VERSION 5.4 ;
NAMESCASESENSITIVE ON ;
BUSBITCHARS "[]" ;
DIVIDERCHAR "/" ;
# PATCHED FOR NEBULA: OpenRAM emits 2000 dbu/um, but the sky130hd tech LEF
# declares 1000 and OpenROAD refuses a macro LEF with a finer factor than the
# technology (ODB-0292). Every coordinate in this file has at most three
# decimals, so 1000 dbu/um represents all of them exactly -- nothing is
# snapped or lost. Original kept alongside as <name>.lef.openram_orig.
UNITS
  DATABASE MICRONS 1000 ;
END UNITS
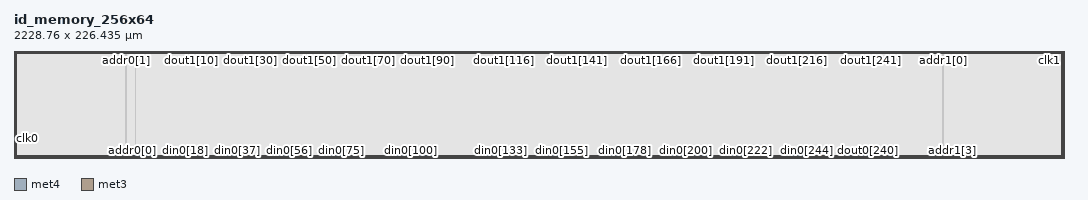
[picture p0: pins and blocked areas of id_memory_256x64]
MACRO id_memory_256x64
   CLASS BLOCK ;
   SIZE 2228.76 BY 226.435 ;
   SYMMETRY X Y R90 ;
   PIN din0[0]
      DIRECTION INPUT ;
      PORT
         LAYER met4 ;
         RECT  257.68 0.0 258.06 0.38 ;
      END
   END din0[0]
   PIN din0[1]
      DIRECTION INPUT ;
      PORT
         LAYER met4 ;
         RECT  263.52 0.0 263.9 0.38 ;
      END
   END din0[1]
   PIN din0[2]
      DIRECTION INPUT ;
      PORT
         LAYER met4 ;
         RECT  269.36 0.0 269.74 0.38 ;
      END
   END din0[2]
   PIN din0[3]
      DIRECTION INPUT ;
      PORT
         LAYER met4 ;
         RECT  275.2 0.0 275.58 0.38 ;
      END
   END din0[3]
   PIN din0[4]
      DIRECTION INPUT ;
      PORT
         LAYER met4 ;
         RECT  281.04 0.0 281.42 0.38 ;
      END
   END din0[4]
   PIN din0[5]
      DIRECTION INPUT ;
      PORT
         LAYER met4 ;
         RECT  286.88 0.0 287.26 0.38 ;
      END
   END din0[5]
   PIN din0[6]
      DIRECTION INPUT ;
      PORT
         LAYER met4 ;
         RECT  292.72 0.0 293.1 0.38 ;
      END
   END din0[6]
   PIN din0[7]
      DIRECTION INPUT ;
      PORT
         LAYER met4 ;
         RECT  298.56 0.0 298.94 0.38 ;
      END
   END din0[7]
   PIN din0[8]
      DIRECTION INPUT ;
      PORT
         LAYER met4 ;
         RECT  304.4 0.0 304.78 0.38 ;
      END
   END din0[8]
   PIN din0[9]
      DIRECTION INPUT ;
      PORT
         LAYER met4 ;
         RECT  310.24 0.0 310.62 0.38 ;
      END
   END din0[9]
   PIN din0[10]
      DIRECTION INPUT ;
      PORT
         LAYER met4 ;
         RECT  316.08 0.0 316.46 0.38 ;
      END
   END din0[10]
   PIN din0[11]
      DIRECTION INPUT ;
      PORT
         LAYER met4 ;
         RECT  321.92 0.0 322.3 0.38 ;
      END
   END din0[11]
   PIN din0[12]
      DIRECTION INPUT ;
      PORT
         LAYER met4 ;
         RECT  327.76 0.0 328.14 0.38 ;
      END
   END din0[12]
   PIN din0[13]
      DIRECTION INPUT ;
      PORT
         LAYER met4 ;
         RECT  333.6 0.0 333.98 0.38 ;
      END
   END din0[13]
   PIN din0[14]
      DIRECTION INPUT ;
      PORT
         LAYER met4 ;
         RECT  339.44 0.0 339.82 0.38 ;
      END
   END din0[14]
   PIN din0[15]
      DIRECTION INPUT ;
      PORT
         LAYER met4 ;
         RECT  345.28 0.0 345.66 0.38 ;
      END
   END din0[15]
   PIN din0[16]
      DIRECTION INPUT ;
      PORT
         LAYER met4 ;
         RECT  351.12 0.0 351.5 0.38 ;
      END
   END din0[16]
   PIN din0[17]
      DIRECTION INPUT ;
      PORT
         LAYER met4 ;
         RECT  356.96 0.0 357.34 0.38 ;
      END
   END din0[17]
   PIN din0[18]
      DIRECTION INPUT ;
      PORT
         LAYER met4 ;
         RECT  362.8 0.0 363.18 0.38 ;
      END
   END din0[18]
   PIN din0[19]
      DIRECTION INPUT ;
      PORT
         LAYER met4 ;
         RECT  368.64 0.0 369.02 0.38 ;
      END
   END din0[19]
   PIN din0[20]
      DIRECTION INPUT ;
      PORT
         LAYER met4 ;
         RECT  374.48 0.0 374.86 0.38 ;
      END
   END din0[20]
   PIN din0[21]
      DIRECTION INPUT ;
      PORT
         LAYER met4 ;
         RECT  380.32 0.0 380.7 0.38 ;
      END
   END din0[21]
   PIN din0[22]
      DIRECTION INPUT ;
      PORT
         LAYER met4 ;
         RECT  386.16 0.0 386.54 0.38 ;
      END
   END din0[22]
   PIN din0[23]
      DIRECTION INPUT ;
      PORT
         LAYER met4 ;
         RECT  392.0 0.0 392.38 0.38 ;
      END
   END din0[23]
   PIN din0[24]
      DIRECTION INPUT ;
      PORT
         LAYER met4 ;
         RECT  397.84 0.0 398.22 0.38 ;
      END
   END din0[24]
   PIN din0[25]
      DIRECTION INPUT ;
      PORT
         LAYER met4 ;
         RECT  403.68 0.0 404.06 0.38 ;
      END
   END din0[25]
   PIN din0[26]
      DIRECTION INPUT ;
      PORT
         LAYER met4 ;
         RECT  409.52 0.0 409.9 0.38 ;
      END
   END din0[26]
   PIN din0[27]
      DIRECTION INPUT ;
      PORT
         LAYER met4 ;
         RECT  415.36 0.0 415.74 0.38 ;
      END
   END din0[27]
   PIN din0[28]
      DIRECTION INPUT ;
      PORT
         LAYER met4 ;
         RECT  421.2 0.0 421.58 0.38 ;
      END
   END din0[28]
   PIN din0[29]
      DIRECTION INPUT ;
      PORT
         LAYER met4 ;
         RECT  427.04 0.0 427.42 0.38 ;
      END
   END din0[29]
   PIN din0[30]
      DIRECTION INPUT ;
      PORT
         LAYER met4 ;
         RECT  432.88 0.0 433.26 0.38 ;
      END
   END din0[30]
   PIN din0[31]
      DIRECTION INPUT ;
      PORT
         LAYER met4 ;
         RECT  438.72 0.0 439.1 0.38 ;
      END
   END din0[31]
   PIN din0[32]
      DIRECTION INPUT ;
      PORT
         LAYER met4 ;
         RECT  444.56 0.0 444.94 0.38 ;
      END
   END din0[32]
   PIN din0[33]
      DIRECTION INPUT ;
      PORT
         LAYER met4 ;
         RECT  450.4 0.0 450.78 0.38 ;
      END
   END din0[33]
   PIN din0[34]
      DIRECTION INPUT ;
      PORT
         LAYER met4 ;
         RECT  456.24 0.0 456.62 0.38 ;
      END
   END din0[34]
   PIN din0[35]
      DIRECTION INPUT ;
      PORT
         LAYER met4 ;
         RECT  462.08 0.0 462.46 0.38 ;
      END
   END din0[35]
   PIN din0[36]
      DIRECTION INPUT ;
      PORT
         LAYER met4 ;
         RECT  467.92 0.0 468.3 0.38 ;
      END
   END din0[36]
   PIN din0[37]
      DIRECTION INPUT ;
      PORT
         LAYER met4 ;
         RECT  473.76 0.0 474.14 0.38 ;
      END
   END din0[37]
   PIN din0[38]
      DIRECTION INPUT ;
      PORT
         LAYER met4 ;
         RECT  479.6 0.0 479.98 0.38 ;
      END
   END din0[38]
   PIN din0[39]
      DIRECTION INPUT ;
      PORT
         LAYER met4 ;
         RECT  485.44 0.0 485.82 0.38 ;
      END
   END din0[39]
   PIN din0[40]
      DIRECTION INPUT ;
      PORT
         LAYER met4 ;
         RECT  491.28 0.0 491.66 0.38 ;
      END
   END din0[40]
   PIN din0[41]
      DIRECTION INPUT ;
      PORT
         LAYER met4 ;
         RECT  497.12 0.0 497.5 0.38 ;
      END
   END din0[41]
   PIN din0[42]
      DIRECTION INPUT ;
      PORT
         LAYER met4 ;
         RECT  502.96 0.0 503.34 0.38 ;
      END
   END din0[42]
   PIN din0[43]
      DIRECTION INPUT ;
      PORT
         LAYER met4 ;
         RECT  508.8 0.0 509.18 0.38 ;
      END
   END din0[43]
   PIN din0[44]
      DIRECTION INPUT ;
      PORT
         LAYER met4 ;
         RECT  514.64 0.0 515.02 0.38 ;
      END
   END din0[44]
   PIN din0[45]
      DIRECTION INPUT ;
      PORT
         LAYER met4 ;
         RECT  520.48 0.0 520.86 0.38 ;
      END
   END din0[45]
   PIN din0[46]
      DIRECTION INPUT ;
      PORT
         LAYER met4 ;
         RECT  526.32 0.0 526.7 0.38 ;
      END
   END din0[46]
   PIN din0[47]
      DIRECTION INPUT ;
      PORT
         LAYER met4 ;
         RECT  532.16 0.0 532.54 0.38 ;
      END
   END din0[47]
   PIN din0[48]
      DIRECTION INPUT ;
      PORT
         LAYER met4 ;
         RECT  538.0 0.0 538.38 0.38 ;
      END
   END din0[48]
   PIN din0[49]
      DIRECTION INPUT ;
      PORT
         LAYER met4 ;
         RECT  543.84 0.0 544.22 0.38 ;
      END
   END din0[49]
   PIN din0[50]
      DIRECTION INPUT ;
      PORT
         LAYER met4 ;
         RECT  549.68 0.0 550.06 0.38 ;
      END
   END din0[50]
   PIN din0[51]
      DIRECTION INPUT ;
      PORT
         LAYER met4 ;
         RECT  555.52 0.0 555.9 0.38 ;
      END
   END din0[51]
   PIN din0[52]
      DIRECTION INPUT ;
      PORT
         LAYER met4 ;
         RECT  561.36 0.0 561.74 0.38 ;
      END
   END din0[52]
   PIN din0[53]
      DIRECTION INPUT ;
      PORT
         LAYER met4 ;
         RECT  567.2 0.0 567.58 0.38 ;
      END
   END din0[53]
   PIN din0[54]
      DIRECTION INPUT ;
      PORT
         LAYER met4 ;
         RECT  573.04 0.0 573.42 0.38 ;
      END
   END din0[54]
   PIN din0[55]
      DIRECTION INPUT ;
      PORT
         LAYER met4 ;
         RECT  578.88 0.0 579.26 0.38 ;
      END
   END din0[55]
   PIN din0[56]
      DIRECTION INPUT ;
      PORT
         LAYER met4 ;
         RECT  584.72 0.0 585.1 0.38 ;
      END
   END din0[56]
   PIN din0[57]
      DIRECTION INPUT ;
      PORT
         LAYER met4 ;
         RECT  590.56 0.0 590.94 0.38 ;
      END
   END din0[57]
   PIN din0[58]
      DIRECTION INPUT ;
      PORT
         LAYER met4 ;
         RECT  596.4 0.0 596.78 0.38 ;
      END
   END din0[58]
   PIN din0[59]
      DIRECTION INPUT ;
      PORT
         LAYER met4 ;
         RECT  602.24 0.0 602.62 0.38 ;
      END
   END din0[59]
   PIN din0[60]
      DIRECTION INPUT ;
      PORT
         LAYER met4 ;
         RECT  608.08 0.0 608.46 0.38 ;
      END
   END din0[60]
   PIN din0[61]
      DIRECTION INPUT ;
      PORT
         LAYER met4 ;
         RECT  613.92 0.0 614.3 0.38 ;
      END
   END din0[61]
   PIN din0[62]
      DIRECTION INPUT ;
      PORT
         LAYER met4 ;
         RECT  619.76 0.0 620.14 0.38 ;
      END
   END din0[62]
   PIN din0[63]
      DIRECTION INPUT ;
      PORT
         LAYER met4 ;
         RECT  625.6 0.0 625.98 0.38 ;
      END
   END din0[63]
   PIN din0[64]
      DIRECTION INPUT ;
      PORT
         LAYER met4 ;
         RECT  631.44 0.0 631.82 0.38 ;
      END
   END din0[64]
   PIN din0[65]
      DIRECTION INPUT ;
      PORT
         LAYER met4 ;
         RECT  637.28 0.0 637.66 0.38 ;
      END
   END din0[65]
   PIN din0[66]
      DIRECTION INPUT ;
      PORT
         LAYER met4 ;
         RECT  643.12 0.0 643.5 0.38 ;
      END
   END din0[66]
   PIN din0[67]
      DIRECTION INPUT ;
      PORT
         LAYER met4 ;
         RECT  648.96 0.0 649.34 0.38 ;
      END
   END din0[67]
   PIN din0[68]
      DIRECTION INPUT ;
      PORT
         LAYER met4 ;
         RECT  654.8 0.0 655.18 0.38 ;
      END
   END din0[68]
   PIN din0[69]
      DIRECTION INPUT ;
      PORT
         LAYER met4 ;
         RECT  660.64 0.0 661.02 0.38 ;
      END
   END din0[69]
   PIN din0[70]
      DIRECTION INPUT ;
      PORT
         LAYER met4 ;
         RECT  666.48 0.0 666.86 0.38 ;
      END
   END din0[70]
   PIN din0[71]
      DIRECTION INPUT ;
      PORT
         LAYER met4 ;
         RECT  672.32 0.0 672.7 0.38 ;
      END
   END din0[71]
   PIN din0[72]
      DIRECTION INPUT ;
      PORT
         LAYER met4 ;
         RECT  678.16 0.0 678.54 0.38 ;
      END
   END din0[72]
   PIN din0[73]
      DIRECTION INPUT ;
      PORT
         LAYER met4 ;
         RECT  684.0 0.0 684.38 0.38 ;
      END
   END din0[73]
   PIN din0[74]
      DIRECTION INPUT ;
      PORT
         LAYER met4 ;
         RECT  689.84 0.0 690.22 0.38 ;
      END
   END din0[74]
   PIN din0[75]
      DIRECTION INPUT ;
      PORT
         LAYER met4 ;
         RECT  695.68 0.0 696.06 0.38 ;
      END
   END din0[75]
   PIN din0[76]
      DIRECTION INPUT ;
      PORT
         LAYER met4 ;
         RECT  701.52 0.0 701.9 0.38 ;
      END
   END din0[76]
   PIN din0[77]
      DIRECTION INPUT ;
      PORT
         LAYER met4 ;
         RECT  707.36 0.0 707.74 0.38 ;
      END
   END din0[77]
   PIN din0[78]
      DIRECTION INPUT ;
      PORT
         LAYER met4 ;
         RECT  713.2 0.0 713.58 0.38 ;
      END
   END din0[78]
   PIN din0[79]
      DIRECTION INPUT ;
      PORT
         LAYER met4 ;
         RECT  719.04 0.0 719.42 0.38 ;
      END
   END din0[79]
   PIN din0[80]
      DIRECTION INPUT ;
      PORT
         LAYER met4 ;
         RECT  724.88 0.0 725.26 0.38 ;
      END
   END din0[80]
   PIN din0[81]
      DIRECTION INPUT ;
      PORT
         LAYER met4 ;
         RECT  730.72 0.0 731.1 0.38 ;
      END
   END din0[81]
   PIN din0[82]
      DIRECTION INPUT ;
      PORT
         LAYER met4 ;
         RECT  736.56 0.0 736.94 0.38 ;
      END
   END din0[82]
   PIN din0[83]
      DIRECTION INPUT ;
      PORT
         LAYER met4 ;
         RECT  742.4 0.0 742.78 0.38 ;
      END
   END din0[83]
   PIN din0[84]
      DIRECTION INPUT ;
      PORT
         LAYER met4 ;
         RECT  748.24 0.0 748.62 0.38 ;
      END
   END din0[84]
   PIN din0[85]
      DIRECTION INPUT ;
      PORT
         LAYER met4 ;
         RECT  754.08 0.0 754.46 0.38 ;
      END
   END din0[85]
   PIN din0[86]
      DIRECTION INPUT ;
      PORT
         LAYER met4 ;
         RECT  759.92 0.0 760.3 0.38 ;
      END
   END din0[86]
   PIN din0[87]
      DIRECTION INPUT ;
      PORT
         LAYER met4 ;
         RECT  765.76 0.0 766.14 0.38 ;
      END
   END din0[87]
   PIN din0[88]
      DIRECTION INPUT ;
      PORT
         LAYER met4 ;
         RECT  771.6 0.0 771.98 0.38 ;
      END
   END din0[88]
   PIN din0[89]
      DIRECTION INPUT ;
      PORT
         LAYER met4 ;
         RECT  777.44 0.0 777.82 0.38 ;
      END
   END din0[89]
   PIN din0[90]
      DIRECTION INPUT ;
      PORT
         LAYER met4 ;
         RECT  783.28 0.0 783.66 0.38 ;
      END
   END din0[90]
   PIN din0[91]
      DIRECTION INPUT ;
      PORT
         LAYER met4 ;
         RECT  789.12 0.0 789.5 0.38 ;
      END
   END din0[91]
   PIN din0[92]
      DIRECTION INPUT ;
      PORT
         LAYER met4 ;
         RECT  794.96 0.0 795.34 0.38 ;
      END
   END din0[92]
   PIN din0[93]
      DIRECTION INPUT ;
      PORT
         LAYER met4 ;
         RECT  800.8 0.0 801.18 0.38 ;
      END
   END din0[93]
   PIN din0[94]
      DIRECTION INPUT ;
      PORT
         LAYER met4 ;
         RECT  806.64 0.0 807.02 0.38 ;
      END
   END din0[94]
   PIN din0[95]
      DIRECTION INPUT ;
      PORT
         LAYER met4 ;
         RECT  812.48 0.0 812.86 0.38 ;
      END
   END din0[95]
   PIN din0[96]
      DIRECTION INPUT ;
      PORT
         LAYER met4 ;
         RECT  818.32 0.0 818.7 0.38 ;
      END
   END din0[96]
   PIN din0[97]
      DIRECTION INPUT ;
      PORT
         LAYER met4 ;
         RECT  824.16 0.0 824.54 0.38 ;
      END
   END din0[97]
   PIN din0[98]
      DIRECTION INPUT ;
      PORT
         LAYER met4 ;
         RECT  830.0 0.0 830.38 0.38 ;
      END
   END din0[98]
   PIN din0[99]
      DIRECTION INPUT ;
      PORT
         LAYER met4 ;
         RECT  835.84 0.0 836.22 0.38 ;
      END
   END din0[99]
   PIN din0[100]
      DIRECTION INPUT ;
      PORT
         LAYER met4 ;
         RECT  841.68 0.0 842.06 0.38 ;
      END
   END din0[100]
   PIN din0[101]
      DIRECTION INPUT ;
      PORT
         LAYER met4 ;
         RECT  847.52 0.0 847.9 0.38 ;
      END
   END din0[101]
   PIN din0[102]
      DIRECTION INPUT ;
      PORT
         LAYER met4 ;
         RECT  853.36 0.0 853.74 0.38 ;
      END
   END din0[102]
   PIN din0[103]
      DIRECTION INPUT ;
      PORT
         LAYER met4 ;
         RECT  859.2 0.0 859.58 0.38 ;
      END
   END din0[103]
   PIN din0[104]
      DIRECTION INPUT ;
      PORT
         LAYER met4 ;
         RECT  865.04 0.0 865.42 0.38 ;
      END
   END din0[104]
   PIN din0[105]
      DIRECTION INPUT ;
      PORT
         LAYER met4 ;
         RECT  870.88 0.0 871.26 0.38 ;
      END
   END din0[105]
   PIN din0[106]
      DIRECTION INPUT ;
      PORT
         LAYER met4 ;
         RECT  876.72 0.0 877.1 0.38 ;
      END
   END din0[106]
   PIN din0[107]
      DIRECTION INPUT ;
      PORT
         LAYER met4 ;
         RECT  882.56 0.0 882.94 0.38 ;
      END
   END din0[107]
   PIN din0[108]
      DIRECTION INPUT ;
      PORT
         LAYER met4 ;
         RECT  888.4 0.0 888.78 0.38 ;
      END
   END din0[108]
   PIN din0[109]
      DIRECTION INPUT ;
      PORT
         LAYER met4 ;
         RECT  894.24 0.0 894.62 0.38 ;
      END
   END din0[109]
   PIN din0[110]
      DIRECTION INPUT ;
      PORT
         LAYER met4 ;
         RECT  900.08 0.0 900.46 0.38 ;
      END
   END din0[110]
   PIN din0[111]
      DIRECTION INPUT ;
      PORT
         LAYER met4 ;
         RECT  905.92 0.0 906.3 0.38 ;
      END
   END din0[111]
   PIN din0[112]
      DIRECTION INPUT ;
      PORT
         LAYER met4 ;
         RECT  911.76 0.0 912.14 0.38 ;
      END
   END din0[112]
   PIN din0[113]
      DIRECTION INPUT ;
      PORT
         LAYER met4 ;
         RECT  917.6 0.0 917.98 0.38 ;
      END
   END din0[113]
   PIN din0[114]
      DIRECTION INPUT ;
      PORT
         LAYER met4 ;
         RECT  923.44 0.0 923.82 0.38 ;
      END
   END din0[114]
   PIN din0[115]
      DIRECTION INPUT ;
      PORT
         LAYER met4 ;
         RECT  929.28 0.0 929.66 0.38 ;
      END
   END din0[115]
   PIN din0[116]
      DIRECTION INPUT ;
      PORT
         LAYER met4 ;
         RECT  935.12 0.0 935.5 0.38 ;
      END
   END din0[116]
   PIN din0[117]
      DIRECTION INPUT ;
      PORT
         LAYER met4 ;
         RECT  940.96 0.0 941.34 0.38 ;
      END
   END din0[117]
   PIN din0[118]
      DIRECTION INPUT ;
      PORT
         LAYER met4 ;
         RECT  946.8 0.0 947.18 0.38 ;
      END
   END din0[118]
   PIN din0[119]
      DIRECTION INPUT ;
      PORT
         LAYER met4 ;
         RECT  952.64 0.0 953.02 0.38 ;
      END
   END din0[119]
   PIN din0[120]
      DIRECTION INPUT ;
      PORT
         LAYER met4 ;
         RECT  958.48 0.0 958.86 0.38 ;
      END
   END din0[120]
   PIN din0[121]
      DIRECTION INPUT ;
      PORT
         LAYER met4 ;
         RECT  964.32 0.0 964.7 0.38 ;
      END
   END din0[121]
   PIN din0[122]
      DIRECTION INPUT ;
      PORT
         LAYER met4 ;
         RECT  970.16 0.0 970.54 0.38 ;
      END
   END din0[122]
   PIN din0[123]
      DIRECTION INPUT ;
      PORT
         LAYER met4 ;
         RECT  976.0 0.0 976.38 0.38 ;
      END
   END din0[123]
   PIN din0[124]
      DIRECTION INPUT ;
      PORT
         LAYER met4 ;
         RECT  981.84 0.0 982.22 0.38 ;
      END
   END din0[124]
   PIN din0[125]
      DIRECTION INPUT ;
      PORT
         LAYER met4 ;
         RECT  987.68 0.0 988.06 0.38 ;
      END
   END din0[125]
   PIN din0[126]
      DIRECTION INPUT ;
      PORT
         LAYER met4 ;
         RECT  993.52 0.0 993.9 0.38 ;
      END
   END din0[126]
   PIN din0[127]
      DIRECTION INPUT ;
      PORT
         LAYER met4 ;
         RECT  999.36 0.0 999.74 0.38 ;
      END
   END din0[127]
   PIN din0[128]
      DIRECTION INPUT ;
      PORT
         LAYER met4 ;
         RECT  1005.2 0.0 1005.58 0.38 ;
      END
   END din0[128]
   PIN din0[129]
      DIRECTION INPUT ;
      PORT
         LAYER met4 ;
         RECT  1011.04 0.0 1011.42 0.38 ;
      END
   END din0[129]
   PIN din0[130]
      DIRECTION INPUT ;
      PORT
         LAYER met4 ;
         RECT  1016.88 0.0 1017.26 0.38 ;
      END
   END din0[130]
   PIN din0[131]
      DIRECTION INPUT ;
      PORT
         LAYER met4 ;
         RECT  1022.72 0.0 1023.1 0.38 ;
      END
   END din0[131]
   PIN din0[132]
      DIRECTION INPUT ;
      PORT
         LAYER met4 ;
         RECT  1028.56 0.0 1028.94 0.38 ;
      END
   END din0[132]
   PIN din0[133]
      DIRECTION INPUT ;
      PORT
         LAYER met4 ;
         RECT  1034.4 0.0 1034.78 0.38 ;
      END
   END din0[133]
   PIN din0[134]
      DIRECTION INPUT ;
      PORT
         LAYER met4 ;
         RECT  1040.24 0.0 1040.62 0.38 ;
      END
   END din0[134]
   PIN din0[135]
      DIRECTION INPUT ;
      PORT
         LAYER met4 ;
         RECT  1046.08 0.0 1046.46 0.38 ;
      END
   END din0[135]
   PIN din0[136]
      DIRECTION INPUT ;
      PORT
         LAYER met4 ;
         RECT  1051.92 0.0 1052.3 0.38 ;
      END
   END din0[136]
   PIN din0[137]
      DIRECTION INPUT ;
      PORT
         LAYER met4 ;
         RECT  1057.76 0.0 1058.14 0.38 ;
      END
   END din0[137]
   PIN din0[138]
      DIRECTION INPUT ;
      PORT
         LAYER met4 ;
         RECT  1063.6 0.0 1063.98 0.38 ;
      END
   END din0[138]
   PIN din0[139]
      DIRECTION INPUT ;
      PORT
         LAYER met4 ;
         RECT  1069.44 0.0 1069.82 0.38 ;
      END
   END din0[139]
   PIN din0[140]
      DIRECTION INPUT ;
      PORT
         LAYER met4 ;
         RECT  1075.28 0.0 1075.66 0.38 ;
      END
   END din0[140]
   PIN din0[141]
      DIRECTION INPUT ;
      PORT
         LAYER met4 ;
         RECT  1081.12 0.0 1081.5 0.38 ;
      END
   END din0[141]
   PIN din0[142]
      DIRECTION INPUT ;
      PORT
         LAYER met4 ;
         RECT  1086.96 0.0 1087.34 0.38 ;
      END
   END din0[142]
   PIN din0[143]
      DIRECTION INPUT ;
      PORT
         LAYER met4 ;
         RECT  1092.8 0.0 1093.18 0.38 ;
      END
   END din0[143]
   PIN din0[144]
      DIRECTION INPUT ;
      PORT
         LAYER met4 ;
         RECT  1098.64 0.0 1099.02 0.38 ;
      END
   END din0[144]
   PIN din0[145]
      DIRECTION INPUT ;
      PORT
         LAYER met4 ;
         RECT  1104.48 0.0 1104.86 0.38 ;
      END
   END din0[145]
   PIN din0[146]
      DIRECTION INPUT ;
      PORT
         LAYER met4 ;
         RECT  1110.32 0.0 1110.7 0.38 ;
      END
   END din0[146]
   PIN din0[147]
      DIRECTION INPUT ;
      PORT
         LAYER met4 ;
         RECT  1116.16 0.0 1116.54 0.38 ;
      END
   END din0[147]
   PIN din0[148]
      DIRECTION INPUT ;
      PORT
         LAYER met4 ;
         RECT  1122.0 0.0 1122.38 0.38 ;
      END
   END din0[148]
   PIN din0[149]
      DIRECTION INPUT ;
      PORT
         LAYER met4 ;
         RECT  1127.84 0.0 1128.22 0.38 ;
      END
   END din0[149]
   PIN din0[150]
      DIRECTION INPUT ;
      PORT
         LAYER met4 ;
         RECT  1133.68 0.0 1134.06 0.38 ;
      END
   END din0[150]
   PIN din0[151]
      DIRECTION INPUT ;
      PORT
         LAYER met4 ;
         RECT  1139.52 0.0 1139.9 0.38 ;
      END
   END din0[151]
   PIN din0[152]
      DIRECTION INPUT ;
      PORT
         LAYER met4 ;
         RECT  1145.36 0.0 1145.74 0.38 ;
      END
   END din0[152]
   PIN din0[153]
      DIRECTION INPUT ;
      PORT
         LAYER met4 ;
         RECT  1151.2 0.0 1151.58 0.38 ;
      END
   END din0[153]
   PIN din0[154]
      DIRECTION INPUT ;
      PORT
         LAYER met4 ;
         RECT  1157.04 0.0 1157.42 0.38 ;
      END
   END din0[154]
   PIN din0[155]
      DIRECTION INPUT ;
      PORT
         LAYER met4 ;
         RECT  1162.88 0.0 1163.26 0.38 ;
      END
   END din0[155]
   PIN din0[156]
      DIRECTION INPUT ;
      PORT
         LAYER met4 ;
         RECT  1168.72 0.0 1169.1 0.38 ;
      END
   END din0[156]
   PIN din0[157]
      DIRECTION INPUT ;
      PORT
         LAYER met4 ;
         RECT  1174.56 0.0 1174.94 0.38 ;
      END
   END din0[157]
   PIN din0[158]
      DIRECTION INPUT ;
      PORT
         LAYER met4 ;
         RECT  1180.4 0.0 1180.78 0.38 ;
      END
   END din0[158]
   PIN din0[159]
      DIRECTION INPUT ;
      PORT
         LAYER met4 ;
         RECT  1186.24 0.0 1186.62 0.38 ;
      END
   END din0[159]
   PIN din0[160]
      DIRECTION INPUT ;
      PORT
         LAYER met4 ;
         RECT  1192.08 0.0 1192.46 0.38 ;
      END
   END din0[160]
   PIN din0[161]
      DIRECTION INPUT ;
      PORT
         LAYER met4 ;
         RECT  1197.92 0.0 1198.3 0.38 ;
      END
   END din0[161]
   PIN din0[162]
      DIRECTION INPUT ;
      PORT
         LAYER met4 ;
         RECT  1203.76 0.0 1204.14 0.38 ;
      END
   END din0[162]
   PIN din0[163]
      DIRECTION INPUT ;
      PORT
         LAYER met4 ;
         RECT  1209.6 0.0 1209.98 0.38 ;
      END
   END din0[163]
   PIN din0[164]
      DIRECTION INPUT ;
      PORT
         LAYER met4 ;
         RECT  1215.44 0.0 1215.82 0.38 ;
      END
   END din0[164]
   PIN din0[165]
      DIRECTION INPUT ;
      PORT
         LAYER met4 ;
         RECT  1221.28 0.0 1221.66 0.38 ;
      END
   END din0[165]
   PIN din0[166]
      DIRECTION INPUT ;
      PORT
         LAYER met4 ;
         RECT  1227.12 0.0 1227.5 0.38 ;
      END
   END din0[166]
   PIN din0[167]
      DIRECTION INPUT ;
      PORT
         LAYER met4 ;
         RECT  1232.96 0.0 1233.34 0.38 ;
      END
   END din0[167]
   PIN din0[168]
      DIRECTION INPUT ;
      PORT
         LAYER met4 ;
         RECT  1238.8 0.0 1239.18 0.38 ;
      END
   END din0[168]
   PIN din0[169]
      DIRECTION INPUT ;
      PORT
         LAYER met4 ;
         RECT  1244.64 0.0 1245.02 0.38 ;
      END
   END din0[169]
   PIN din0[170]
      DIRECTION INPUT ;
      PORT
         LAYER met4 ;
         RECT  1250.48 0.0 1250.86 0.38 ;
      END
   END din0[170]
   PIN din0[171]
      DIRECTION INPUT ;
      PORT
         LAYER met4 ;
         RECT  1256.32 0.0 1256.7 0.38 ;
      END
   END din0[171]
   PIN din0[172]
      DIRECTION INPUT ;
      PORT
         LAYER met4 ;
         RECT  1262.16 0.0 1262.54 0.38 ;
      END
   END din0[172]
   PIN din0[173]
      DIRECTION INPUT ;
      PORT
         LAYER met4 ;
         RECT  1268.0 0.0 1268.38 0.38 ;
      END
   END din0[173]
   PIN din0[174]
      DIRECTION INPUT ;
      PORT
         LAYER met4 ;
         RECT  1273.84 0.0 1274.22 0.38 ;
      END
   END din0[174]
   PIN din0[175]
      DIRECTION INPUT ;
      PORT
         LAYER met4 ;
         RECT  1279.68 0.0 1280.06 0.38 ;
      END
   END din0[175]
   PIN din0[176]
      DIRECTION INPUT ;
      PORT
         LAYER met4 ;
         RECT  1285.52 0.0 1285.9 0.38 ;
      END
   END din0[176]
   PIN din0[177]
      DIRECTION INPUT ;
      PORT
         LAYER met4 ;
         RECT  1291.36 0.0 1291.74 0.38 ;
      END
   END din0[177]
   PIN din0[178]
      DIRECTION INPUT ;
      PORT
         LAYER met4 ;
         RECT  1297.2 0.0 1297.58 0.38 ;
      END
   END din0[178]
   PIN din0[179]
      DIRECTION INPUT ;
      PORT
         LAYER met4 ;
         RECT  1303.04 0.0 1303.42 0.38 ;
      END
   END din0[179]
   PIN din0[180]
      DIRECTION INPUT ;
      PORT
         LAYER met4 ;
         RECT  1308.88 0.0 1309.26 0.38 ;
      END
   END din0[180]
   PIN din0[181]
      DIRECTION INPUT ;
      PORT
         LAYER met4 ;
         RECT  1314.72 0.0 1315.1 0.38 ;
      END
   END din0[181]
   PIN din0[182]
      DIRECTION INPUT ;
      PORT
         LAYER met4 ;
         RECT  1320.56 0.0 1320.94 0.38 ;
      END
   END din0[182]
   PIN din0[183]
      DIRECTION INPUT ;
      PORT
         LAYER met4 ;
         RECT  1326.4 0.0 1326.78 0.38 ;
      END
   END din0[183]
   PIN din0[184]
      DIRECTION INPUT ;
      PORT
         LAYER met4 ;
         RECT  1332.24 0.0 1332.62 0.38 ;
      END
   END din0[184]
   PIN din0[185]
      DIRECTION INPUT ;
      PORT
         LAYER met4 ;
         RECT  1338.08 0.0 1338.46 0.38 ;
      END
   END din0[185]
   PIN din0[186]
      DIRECTION INPUT ;
      PORT
         LAYER met4 ;
         RECT  1343.92 0.0 1344.3 0.38 ;
      END
   END din0[186]
   PIN din0[187]
      DIRECTION INPUT ;
      PORT
         LAYER met4 ;
         RECT  1349.76 0.0 1350.14 0.38 ;
      END
   END din0[187]
   PIN din0[188]
      DIRECTION INPUT ;
      PORT
         LAYER met4 ;
         RECT  1355.6 0.0 1355.98 0.38 ;
      END
   END din0[188]
   PIN din0[189]
      DIRECTION INPUT ;
      PORT
         LAYER met4 ;
         RECT  1361.44 0.0 1361.82 0.38 ;
      END
   END din0[189]
   PIN din0[190]
      DIRECTION INPUT ;
      PORT
         LAYER met4 ;
         RECT  1367.28 0.0 1367.66 0.38 ;
      END
   END din0[190]
   PIN din0[191]
      DIRECTION INPUT ;
      PORT
         LAYER met4 ;
         RECT  1373.12 0.0 1373.5 0.38 ;
      END
   END din0[191]
   PIN din0[192]
      DIRECTION INPUT ;
      PORT
         LAYER met4 ;
         RECT  1378.96 0.0 1379.34 0.38 ;
      END
   END din0[192]
   PIN din0[193]
      DIRECTION INPUT ;
      PORT
         LAYER met4 ;
         RECT  1384.8 0.0 1385.18 0.38 ;
      END
   END din0[193]
   PIN din0[194]
      DIRECTION INPUT ;
      PORT
         LAYER met4 ;
         RECT  1390.64 0.0 1391.02 0.38 ;
      END
   END din0[194]
   PIN din0[195]
      DIRECTION INPUT ;
      PORT
         LAYER met4 ;
         RECT  1396.48 0.0 1396.86 0.38 ;
      END
   END din0[195]
   PIN din0[196]
      DIRECTION INPUT ;
      PORT
         LAYER met4 ;
         RECT  1402.32 0.0 1402.7 0.38 ;
      END
   END din0[196]
   PIN din0[197]
      DIRECTION INPUT ;
      PORT
         LAYER met4 ;
         RECT  1408.16 0.0 1408.54 0.38 ;
      END
   END din0[197]
   PIN din0[198]
      DIRECTION INPUT ;
      PORT
         LAYER met4 ;
         RECT  1414.0 0.0 1414.38 0.38 ;
      END
   END din0[198]
   PIN din0[199]
      DIRECTION INPUT ;
      PORT
         LAYER met4 ;
         RECT  1419.84 0.0 1420.22 0.38 ;
      END
   END din0[199]
   PIN din0[200]
      DIRECTION INPUT ;
      PORT
         LAYER met4 ;
         RECT  1425.68 0.0 1426.06 0.38 ;
      END
   END din0[200]
   PIN din0[201]
      DIRECTION INPUT ;
      PORT
         LAYER met4 ;
         RECT  1431.52 0.0 1431.9 0.38 ;
      END
   END din0[201]
   PIN din0[202]
      DIRECTION INPUT ;
      PORT
         LAYER met4 ;
         RECT  1437.36 0.0 1437.74 0.38 ;
      END
   END din0[202]
   PIN din0[203]
      DIRECTION INPUT ;
      PORT
         LAYER met4 ;
         RECT  1443.2 0.0 1443.58 0.38 ;
      END
   END din0[203]
   PIN din0[204]
      DIRECTION INPUT ;
      PORT
         LAYER met4 ;
         RECT  1449.04 0.0 1449.42 0.38 ;
      END
   END din0[204]
   PIN din0[205]
      DIRECTION INPUT ;
      PORT
         LAYER met4 ;
         RECT  1454.88 0.0 1455.26 0.38 ;
      END
   END din0[205]
   PIN din0[206]
      DIRECTION INPUT ;
      PORT
         LAYER met4 ;
         RECT  1460.72 0.0 1461.1 0.38 ;
      END
   END din0[206]
   PIN din0[207]
      DIRECTION INPUT ;
      PORT
         LAYER met4 ;
         RECT  1466.56 0.0 1466.94 0.38 ;
      END
   END din0[207]
   PIN din0[208]
      DIRECTION INPUT ;
      PORT
         LAYER met4 ;
         RECT  1472.4 0.0 1472.78 0.38 ;
      END
   END din0[208]
   PIN din0[209]
      DIRECTION INPUT ;
      PORT
         LAYER met4 ;
         RECT  1478.24 0.0 1478.62 0.38 ;
      END
   END din0[209]
   PIN din0[210]
      DIRECTION INPUT ;
      PORT
         LAYER met4 ;
         RECT  1484.08 0.0 1484.46 0.38 ;
      END
   END din0[210]
   PIN din0[211]
      DIRECTION INPUT ;
      PORT
         LAYER met4 ;
         RECT  1489.92 0.0 1490.3 0.38 ;
      END
   END din0[211]
   PIN din0[212]
      DIRECTION INPUT ;
      PORT
         LAYER met4 ;
         RECT  1495.76 0.0 1496.14 0.38 ;
      END
   END din0[212]
   PIN din0[213]
      DIRECTION INPUT ;
      PORT
         LAYER met4 ;
         RECT  1501.6 0.0 1501.98 0.38 ;
      END
   END din0[213]
   PIN din0[214]
      DIRECTION INPUT ;
      PORT
         LAYER met4 ;
         RECT  1507.44 0.0 1507.82 0.38 ;
      END
   END din0[214]
   PIN din0[215]
      DIRECTION INPUT ;
      PORT
         LAYER met4 ;
         RECT  1513.28 0.0 1513.66 0.38 ;
      END
   END din0[215]
   PIN din0[216]
      DIRECTION INPUT ;
      PORT
         LAYER met4 ;
         RECT  1519.12 0.0 1519.5 0.38 ;
      END
   END din0[216]
   PIN din0[217]
      DIRECTION INPUT ;
      PORT
         LAYER met4 ;
         RECT  1524.96 0.0 1525.34 0.38 ;
      END
   END din0[217]
   PIN din0[218]
      DIRECTION INPUT ;
      PORT
         LAYER met4 ;
         RECT  1530.8 0.0 1531.18 0.38 ;
      END
   END din0[218]
   PIN din0[219]
      DIRECTION INPUT ;
      PORT
         LAYER met4 ;
         RECT  1536.64 0.0 1537.02 0.38 ;
      END
   END din0[219]
   PIN din0[220]
      DIRECTION INPUT ;
      PORT
         LAYER met4 ;
         RECT  1542.48 0.0 1542.86 0.38 ;
      END
   END din0[220]
   PIN din0[221]
      DIRECTION INPUT ;
      PORT
         LAYER met4 ;
         RECT  1548.32 0.0 1548.7 0.38 ;
      END
   END din0[221]
   PIN din0[222]
      DIRECTION INPUT ;
      PORT
         LAYER met4 ;
         RECT  1554.16 0.0 1554.54 0.38 ;
      END
   END din0[222]
   PIN din0[223]
      DIRECTION INPUT ;
      PORT
         LAYER met4 ;
         RECT  1560.0 0.0 1560.38 0.38 ;
      END
   END din0[223]
   PIN din0[224]
      DIRECTION INPUT ;
      PORT
         LAYER met4 ;
         RECT  1565.84 0.0 1566.22 0.38 ;
      END
   END din0[224]
   PIN din0[225]
      DIRECTION INPUT ;
      PORT
         LAYER met4 ;
         RECT  1571.68 0.0 1572.06 0.38 ;
      END
   END din0[225]
   PIN din0[226]
      DIRECTION INPUT ;
      PORT
         LAYER met4 ;
         RECT  1577.52 0.0 1577.9 0.38 ;
      END
   END din0[226]
   PIN din0[227]
      DIRECTION INPUT ;
      PORT
         LAYER met4 ;
         RECT  1583.36 0.0 1583.74 0.38 ;
      END
   END din0[227]
   PIN din0[228]
      DIRECTION INPUT ;
      PORT
         LAYER met4 ;
         RECT  1589.2 0.0 1589.58 0.38 ;
      END
   END din0[228]
   PIN din0[229]
      DIRECTION INPUT ;
      PORT
         LAYER met4 ;
         RECT  1595.04 0.0 1595.42 0.38 ;
      END
   END din0[229]
   PIN din0[230]
      DIRECTION INPUT ;
      PORT
         LAYER met4 ;
         RECT  1600.88 0.0 1601.26 0.38 ;
      END
   END din0[230]
   PIN din0[231]
      DIRECTION INPUT ;
      PORT
         LAYER met4 ;
         RECT  1606.72 0.0 1607.1 0.38 ;
      END
   END din0[231]
   PIN din0[232]
      DIRECTION INPUT ;
      PORT
         LAYER met4 ;
         RECT  1612.56 0.0 1612.94 0.38 ;
      END
   END din0[232]
   PIN din0[233]
      DIRECTION INPUT ;
      PORT
         LAYER met4 ;
         RECT  1618.4 0.0 1618.78 0.38 ;
      END
   END din0[233]
   PIN din0[234]
      DIRECTION INPUT ;
      PORT
         LAYER met4 ;
         RECT  1624.24 0.0 1624.62 0.38 ;
      END
   END din0[234]
   PIN din0[235]
      DIRECTION INPUT ;
      PORT
         LAYER met4 ;
         RECT  1630.08 0.0 1630.46 0.38 ;
      END
   END din0[235]
   PIN din0[236]
      DIRECTION INPUT ;
      PORT
         LAYER met4 ;
         RECT  1635.92 0.0 1636.3 0.38 ;
      END
   END din0[236]
   PIN din0[237]
      DIRECTION INPUT ;
      PORT
         LAYER met4 ;
         RECT  1641.76 0.0 1642.14 0.38 ;
      END
   END din0[237]
   PIN din0[238]
      DIRECTION INPUT ;
      PORT
         LAYER met4 ;
         RECT  1647.6 0.0 1647.98 0.38 ;
      END
   END din0[238]
   PIN din0[239]
      DIRECTION INPUT ;
      PORT
         LAYER met4 ;
         RECT  1653.44 0.0 1653.82 0.38 ;
      END
   END din0[239]
   PIN din0[240]
      DIRECTION INPUT ;
      PORT
         LAYER met4 ;
         RECT  1659.28 0.0 1659.66 0.38 ;
      END
   END din0[240]
   PIN din0[241]
      DIRECTION INPUT ;
      PORT
         LAYER met4 ;
         RECT  1665.12 0.0 1665.5 0.38 ;
      END
   END din0[241]
   PIN din0[242]
      DIRECTION INPUT ;
      PORT
         LAYER met4 ;
         RECT  1670.96 0.0 1671.34 0.38 ;
      END
   END din0[242]
   PIN din0[243]
      DIRECTION INPUT ;
      PORT
         LAYER met4 ;
         RECT  1676.8 0.0 1677.18 0.38 ;
      END
   END din0[243]
   PIN din0[244]
      DIRECTION INPUT ;
      PORT
         LAYER met4 ;
         RECT  1682.64 0.0 1683.02 0.38 ;
      END
   END din0[244]
   PIN din0[245]
      DIRECTION INPUT ;
      PORT
         LAYER met4 ;
         RECT  1688.48 0.0 1688.86 0.38 ;
      END
   END din0[245]
   PIN din0[246]
      DIRECTION INPUT ;
      PORT
         LAYER met4 ;
         RECT  1694.32 0.0 1694.7 0.38 ;
      END
   END din0[246]
   PIN din0[247]
      DIRECTION INPUT ;
      PORT
         LAYER met4 ;
         RECT  1700.16 0.0 1700.54 0.38 ;
      END
   END din0[247]
   PIN din0[248]
      DIRECTION INPUT ;
      PORT
         LAYER met4 ;
         RECT  1706.0 0.0 1706.38 0.38 ;
      END
   END din0[248]
   PIN din0[249]
      DIRECTION INPUT ;
      PORT
         LAYER met4 ;
         RECT  1711.84 0.0 1712.22 0.38 ;
      END
   END din0[249]
   PIN din0[250]
      DIRECTION INPUT ;
      PORT
         LAYER met4 ;
         RECT  1717.68 0.0 1718.06 0.38 ;
      END
   END din0[250]
   PIN din0[251]
      DIRECTION INPUT ;
      PORT
         LAYER met4 ;
         RECT  1723.52 0.0 1723.9 0.38 ;
      END
   END din0[251]
   PIN din0[252]
      DIRECTION INPUT ;
      PORT
         LAYER met4 ;
         RECT  1729.36 0.0 1729.74 0.38 ;
      END
   END din0[252]
   PIN din0[253]
      DIRECTION INPUT ;
      PORT
         LAYER met4 ;
         RECT  1735.2 0.0 1735.58 0.38 ;
      END
   END din0[253]
   PIN din0[254]
      DIRECTION INPUT ;
      PORT
         LAYER met4 ;
         RECT  1741.04 0.0 1741.42 0.38 ;
      END
   END din0[254]
   PIN din0[255]
      DIRECTION INPUT ;
      PORT
         LAYER met4 ;
         RECT  1746.88 0.0 1747.26 0.38 ;
      END
   END din0[255]
   PIN din0[256]
      DIRECTION INPUT ;
      PORT
         LAYER met4 ;
         RECT  1752.72 0.0 1753.1 0.38 ;
      END
   END din0[256]
   PIN addr0[0]
      DIRECTION INPUT ;
      PORT
         LAYER met4 ;
         RECT  251.84 0.0 252.22 0.38 ;
      END
   END addr0[0]
   PIN addr0[1]
      DIRECTION INPUT ;
      PORT
         LAYER met4 ;
         RECT  237.93 226.055 238.31 226.435 ;
      END
   END addr0[1]
   PIN addr0[2]
      DIRECTION INPUT ;
      PORT
         LAYER met4 ;
         RECT  242.285 226.055 242.665 226.435 ;
      END
   END addr0[2]
   PIN addr0[3]
      DIRECTION INPUT ;
      PORT
         LAYER met4 ;
         RECT  238.62 226.055 239.0 226.435 ;
      END
   END addr0[3]
   PIN addr0[4]
      DIRECTION INPUT ;
      PORT
         LAYER met4 ;
         RECT  241.595 226.055 241.975 226.435 ;
      END
   END addr0[4]
   PIN addr0[5]
      DIRECTION INPUT ;
      PORT
         LAYER met4 ;
         RECT  240.905 226.055 241.285 226.435 ;
      END
   END addr0[5]
   PIN addr0[6]
      DIRECTION INPUT ;
      PORT
         LAYER met4 ;
         RECT  240.16 226.055 240.54 226.435 ;
      END
   END addr0[6]
   PIN addr1[0]
      DIRECTION INPUT ;
      PORT
         LAYER met4 ;
         RECT  1972.08 226.055 1972.46 226.435 ;
      END
   END addr1[0]
   PIN addr1[1]
      DIRECTION INPUT ;
      PORT
         LAYER met4 ;
         RECT  1991.83 0.0 1992.21 0.38 ;
      END
   END addr1[1]
   PIN addr1[2]
      DIRECTION INPUT ;
      PORT
         LAYER met4 ;
         RECT  1987.475 0.0 1987.855 0.38 ;
      END
   END addr1[2]
   PIN addr1[3]
      DIRECTION INPUT ;
      PORT
         LAYER met4 ;
         RECT  1991.14 0.0 1991.52 0.38 ;
      END
   END addr1[3]
   PIN addr1[4]
      DIRECTION INPUT ;
      PORT
         LAYER met4 ;
         RECT  1988.165 0.0 1988.545 0.38 ;
      END
   END addr1[4]
   PIN addr1[5]
      DIRECTION INPUT ;
      PORT
         LAYER met4 ;
         RECT  1988.855 0.0 1989.235 0.38 ;
      END
   END addr1[5]
   PIN addr1[6]
      DIRECTION INPUT ;
      PORT
         LAYER met4 ;
         RECT  1989.6 0.0 1989.98 0.38 ;
      END
   END addr1[6]
   PIN csb0
      DIRECTION INPUT ;
      PORT
         LAYER met3 ;
         RECT  0.0 41.305 0.38 41.685 ;
      END
   END csb0
   PIN csb1
      DIRECTION INPUT ;
      PORT
         LAYER met3 ;
         RECT  2228.38 211.875 2228.76 212.255 ;
      END
   END csb1
   PIN web0
      DIRECTION INPUT ;
      PORT
         LAYER met3 ;
         RECT  0.0 49.805 0.38 50.185 ;
      END
   END web0
   PIN clk0
      DIRECTION INPUT ;
      PORT
         LAYER met3 ;
         RECT  0.0 42.05 0.38 42.43 ;
      END
   END clk0
   PIN clk1
      DIRECTION INPUT ;
      PORT
         LAYER met4 ;
         RECT  2198.12 226.055 2198.5 226.435 ;
      END
   END clk1
   PIN spare_wen0
      DIRECTION INPUT ;
      PORT
         LAYER met4 ;
         RECT  1758.56 0.0 1758.94 0.38 ;
      END
   END spare_wen0
   PIN dout0[0]
      DIRECTION OUTPUT ;
      PORT
         LAYER met4 ;
         RECT  314.275 0.0 314.655 0.38 ;
      END
   END dout0[0]
   PIN dout0[1]
      DIRECTION OUTPUT ;
      PORT
         LAYER met4 ;
         RECT  320.115 0.0 320.495 0.38 ;
      END
   END dout0[1]
   PIN dout0[2]
      DIRECTION OUTPUT ;
      PORT
         LAYER met4 ;
         RECT  328.825 0.0 329.205 0.38 ;
      END
   END dout0[2]
   PIN dout0[3]
      DIRECTION OUTPUT ;
      PORT
         LAYER met4 ;
         RECT  334.29 0.0 334.67 0.38 ;
      END
   END dout0[3]
   PIN dout0[4]
      DIRECTION OUTPUT ;
      PORT
         LAYER met4 ;
         RECT  340.13 0.0 340.51 0.38 ;
      END
   END dout0[4]
   PIN dout0[5]
      DIRECTION OUTPUT ;
      PORT
         LAYER met4 ;
         RECT  346.165 0.0 346.545 0.38 ;
      END
   END dout0[5]
   PIN dout0[6]
      DIRECTION OUTPUT ;
      PORT
         LAYER met4 ;
         RECT  352.405 0.0 352.785 0.38 ;
      END
   END dout0[6]
   PIN dout0[7]
      DIRECTION OUTPUT ;
      PORT
         LAYER met4 ;
         RECT  358.645 0.0 359.025 0.38 ;
      END
   END dout0[7]
   PIN dout0[8]
      DIRECTION OUTPUT ;
      PORT
         LAYER met4 ;
         RECT  364.885 0.0 365.265 0.38 ;
      END
   END dout0[8]
   PIN dout0[9]
      DIRECTION OUTPUT ;
      PORT
         LAYER met4 ;
         RECT  371.125 0.0 371.505 0.38 ;
      END
   END dout0[9]
   PIN dout0[10]
      DIRECTION OUTPUT ;
      PORT
         LAYER met4 ;
         RECT  377.365 0.0 377.745 0.38 ;
      END
   END dout0[10]
   PIN dout0[11]
      DIRECTION OUTPUT ;
      PORT
         LAYER met4 ;
         RECT  383.605 0.0 383.985 0.38 ;
      END
   END dout0[11]
   PIN dout0[12]
      DIRECTION OUTPUT ;
      PORT
         LAYER met4 ;
         RECT  389.845 0.0 390.225 0.38 ;
      END
   END dout0[12]
   PIN dout0[13]
      DIRECTION OUTPUT ;
      PORT
         LAYER met4 ;
         RECT  396.035 0.0 396.415 0.38 ;
      END
   END dout0[13]
   PIN dout0[14]
      DIRECTION OUTPUT ;
      PORT
         LAYER met4 ;
         RECT  401.64 0.0 402.02 0.38 ;
      END
   END dout0[14]
   PIN dout0[15]
      DIRECTION OUTPUT ;
      PORT
         LAYER met4 ;
         RECT  407.715 0.0 408.095 0.38 ;
      END
   END dout0[15]
   PIN dout0[16]
      DIRECTION OUTPUT ;
      PORT
         LAYER met4 ;
         RECT  413.555 0.0 413.935 0.38 ;
      END
   END dout0[16]
   PIN dout0[17]
      DIRECTION OUTPUT ;
      PORT
         LAYER met4 ;
         RECT  422.425 0.0 422.805 0.38 ;
      END
   END dout0[17]
   PIN dout0[18]
      DIRECTION OUTPUT ;
      PORT
         LAYER met4 ;
         RECT  427.73 0.0 428.11 0.38 ;
      END
   END dout0[18]
   PIN dout0[19]
      DIRECTION OUTPUT ;
      PORT
         LAYER met4 ;
         RECT  433.585 0.0 433.965 0.38 ;
      END
   END dout0[19]
   PIN dout0[20]
      DIRECTION OUTPUT ;
      PORT
         LAYER met4 ;
         RECT  439.765 0.0 440.145 0.38 ;
      END
   END dout0[20]
   PIN dout0[21]
      DIRECTION OUTPUT ;
      PORT
         LAYER met4 ;
         RECT  446.005 0.0 446.385 0.38 ;
      END
   END dout0[21]
   PIN dout0[22]
      DIRECTION OUTPUT ;
      PORT
         LAYER met4 ;
         RECT  452.245 0.0 452.625 0.38 ;
      END
   END dout0[22]
   PIN dout0[23]
      DIRECTION OUTPUT ;
      PORT
         LAYER met4 ;
         RECT  458.485 0.0 458.865 0.38 ;
      END
   END dout0[23]
   PIN dout0[24]
      DIRECTION OUTPUT ;
      PORT
         LAYER met4 ;
         RECT  464.725 0.0 465.105 0.38 ;
      END
   END dout0[24]
   PIN dout0[25]
      DIRECTION OUTPUT ;
      PORT
         LAYER met4 ;
         RECT  470.965 0.0 471.345 0.38 ;
      END
   END dout0[25]
   PIN dout0[26]
      DIRECTION OUTPUT ;
      PORT
         LAYER met4 ;
         RECT  477.205 0.0 477.585 0.38 ;
      END
   END dout0[26]
   PIN dout0[27]
      DIRECTION OUTPUT ;
      PORT
         LAYER met4 ;
         RECT  483.445 0.0 483.825 0.38 ;
      END
   END dout0[27]
   PIN dout0[28]
      DIRECTION OUTPUT ;
      PORT
         LAYER met4 ;
         RECT  489.475 0.0 489.855 0.38 ;
      END
   END dout0[28]
   PIN dout0[29]
      DIRECTION OUTPUT ;
      PORT
         LAYER met4 ;
         RECT  495.24 0.0 495.62 0.38 ;
      END
   END dout0[29]
   PIN dout0[30]
      DIRECTION OUTPUT ;
      PORT
         LAYER met4 ;
         RECT  501.155 0.0 501.535 0.38 ;
      END
   END dout0[30]
   PIN dout0[31]
      DIRECTION OUTPUT ;
      PORT
         LAYER met4 ;
         RECT  509.785 0.0 510.165 0.38 ;
      END
   END dout0[31]
   PIN dout0[32]
      DIRECTION OUTPUT ;
      PORT
         LAYER met4 ;
         RECT  515.33 0.0 515.71 0.38 ;
      END
   END dout0[32]
   PIN dout0[33]
      DIRECTION OUTPUT ;
      PORT
         LAYER met4 ;
         RECT  521.17 0.0 521.55 0.38 ;
      END
   END dout0[33]
   PIN dout0[34]
      DIRECTION OUTPUT ;
      PORT
         LAYER met4 ;
         RECT  527.125 0.0 527.505 0.38 ;
      END
   END dout0[34]
   PIN dout0[35]
      DIRECTION OUTPUT ;
      PORT
         LAYER met4 ;
         RECT  533.365 0.0 533.745 0.38 ;
      END
   END dout0[35]
   PIN dout0[36]
      DIRECTION OUTPUT ;
      PORT
         LAYER met4 ;
         RECT  539.605 0.0 539.985 0.38 ;
      END
   END dout0[36]
   PIN dout0[37]
      DIRECTION OUTPUT ;
      PORT
         LAYER met4 ;
         RECT  545.845 0.0 546.225 0.38 ;
      END
   END dout0[37]
   PIN dout0[38]
      DIRECTION OUTPUT ;
      PORT
         LAYER met4 ;
         RECT  552.085 0.0 552.465 0.38 ;
      END
   END dout0[38]
   PIN dout0[39]
      DIRECTION OUTPUT ;
      PORT
         LAYER met4 ;
         RECT  558.325 0.0 558.705 0.38 ;
      END
   END dout0[39]
   PIN dout0[40]
      DIRECTION OUTPUT ;
      PORT
         LAYER met4 ;
         RECT  564.565 0.0 564.945 0.38 ;
      END
   END dout0[40]
   PIN dout0[41]
      DIRECTION OUTPUT ;
      PORT
         LAYER met4 ;
         RECT  570.805 0.0 571.185 0.38 ;
      END
   END dout0[41]
   PIN dout0[42]
      DIRECTION OUTPUT ;
      PORT
         LAYER met4 ;
         RECT  577.045 0.0 577.425 0.38 ;
      END
   END dout0[42]
   PIN dout0[43]
      DIRECTION OUTPUT ;
      PORT
         LAYER met4 ;
         RECT  582.915 0.0 583.295 0.38 ;
      END
   END dout0[43]
   PIN dout0[44]
      DIRECTION OUTPUT ;
      PORT
         LAYER met4 ;
         RECT  588.755 0.0 589.135 0.38 ;
      END
   END dout0[44]
   PIN dout0[45]
      DIRECTION OUTPUT ;
      PORT
         LAYER met4 ;
         RECT  594.595 0.0 594.975 0.38 ;
      END
   END dout0[45]
   PIN dout0[46]
      DIRECTION OUTPUT ;
      PORT
         LAYER met4 ;
         RECT  603.385 0.0 603.765 0.38 ;
      END
   END dout0[46]
   PIN dout0[47]
      DIRECTION OUTPUT ;
      PORT
         LAYER met4 ;
         RECT  608.77 0.0 609.15 0.38 ;
      END
   END dout0[47]
   PIN dout0[48]
      DIRECTION OUTPUT ;
      PORT
         LAYER met4 ;
         RECT  614.61 0.0 614.99 0.38 ;
      END
   END dout0[48]
   PIN dout0[49]
      DIRECTION OUTPUT ;
      PORT
         LAYER met4 ;
         RECT  620.725 0.0 621.105 0.38 ;
      END
   END dout0[49]
   PIN dout0[50]
      DIRECTION OUTPUT ;
      PORT
         LAYER met4 ;
         RECT  626.965 0.0 627.345 0.38 ;
      END
   END dout0[50]
   PIN dout0[51]
      DIRECTION OUTPUT ;
      PORT
         LAYER met4 ;
         RECT  633.205 0.0 633.585 0.38 ;
      END
   END dout0[51]
   PIN dout0[52]
      DIRECTION OUTPUT ;
      PORT
         LAYER met4 ;
         RECT  639.445 0.0 639.825 0.38 ;
      END
   END dout0[52]
   PIN dout0[53]
      DIRECTION OUTPUT ;
      PORT
         LAYER met4 ;
         RECT  645.685 0.0 646.065 0.38 ;
      END
   END dout0[53]
   PIN dout0[54]
      DIRECTION OUTPUT ;
      PORT
         LAYER met4 ;
         RECT  651.925 0.0 652.305 0.38 ;
      END
   END dout0[54]
   PIN dout0[55]
      DIRECTION OUTPUT ;
      PORT
         LAYER met4 ;
         RECT  658.165 0.0 658.545 0.38 ;
      END
   END dout0[55]
   PIN dout0[56]
      DIRECTION OUTPUT ;
      PORT
         LAYER met4 ;
         RECT  664.405 0.0 664.785 0.38 ;
      END
   END dout0[56]
   PIN dout0[57]
      DIRECTION OUTPUT ;
      PORT
         LAYER met4 ;
         RECT  670.515 0.0 670.895 0.38 ;
      END
   END dout0[57]
   PIN dout0[58]
      DIRECTION OUTPUT ;
      PORT
         LAYER met4 ;
         RECT  676.2 0.0 676.58 0.38 ;
      END
   END dout0[58]
   PIN dout0[59]
      DIRECTION OUTPUT ;
      PORT
         LAYER met4 ;
         RECT  682.195 0.0 682.575 0.38 ;
      END
   END dout0[59]
   PIN dout0[60]
      DIRECTION OUTPUT ;
      PORT
         LAYER met4 ;
         RECT  690.745 0.0 691.125 0.38 ;
      END
   END dout0[60]
   PIN dout0[61]
      DIRECTION OUTPUT ;
      PORT
         LAYER met4 ;
         RECT  696.37 0.0 696.75 0.38 ;
      END
   END dout0[61]
   PIN dout0[62]
      DIRECTION OUTPUT ;
      PORT
         LAYER met4 ;
         RECT  702.21 0.0 702.59 0.38 ;
      END
   END dout0[62]
   PIN dout0[63]
      DIRECTION OUTPUT ;
      PORT
         LAYER met4 ;
         RECT  708.085 0.0 708.465 0.38 ;
      END
   END dout0[63]
   PIN dout0[64]
      DIRECTION OUTPUT ;
      PORT
         LAYER met4 ;
         RECT  714.325 0.0 714.705 0.38 ;
      END
   END dout0[64]
   PIN dout0[65]
      DIRECTION OUTPUT ;
      PORT
         LAYER met4 ;
         RECT  720.565 0.0 720.945 0.38 ;
      END
   END dout0[65]
   PIN dout0[66]
      DIRECTION OUTPUT ;
      PORT
         LAYER met4 ;
         RECT  726.805 0.0 727.185 0.38 ;
      END
   END dout0[66]
   PIN dout0[67]
      DIRECTION OUTPUT ;
      PORT
         LAYER met4 ;
         RECT  733.045 0.0 733.425 0.38 ;
      END
   END dout0[67]
   PIN dout0[68]
      DIRECTION OUTPUT ;
      PORT
         LAYER met4 ;
         RECT  739.285 0.0 739.665 0.38 ;
      END
   END dout0[68]
   PIN dout0[69]
      DIRECTION OUTPUT ;
      PORT
         LAYER met4 ;
         RECT  745.525 0.0 745.905 0.38 ;
      END
   END dout0[69]
   PIN dout0[70]
      DIRECTION OUTPUT ;
      PORT
         LAYER met4 ;
         RECT  751.765 0.0 752.145 0.38 ;
      END
   END dout0[70]
   PIN dout0[71]
      DIRECTION OUTPUT ;
      PORT
         LAYER met4 ;
         RECT  758.005 0.0 758.385 0.38 ;
      END
   END dout0[71]
   PIN dout0[72]
      DIRECTION OUTPUT ;
      PORT
         LAYER met4 ;
         RECT  763.955 0.0 764.335 0.38 ;
      END
   END dout0[72]
   PIN dout0[73]
      DIRECTION OUTPUT ;
      PORT
         LAYER met4 ;
         RECT  769.795 0.0 770.175 0.38 ;
      END
   END dout0[73]
   PIN dout0[74]
      DIRECTION OUTPUT ;
      PORT
         LAYER met4 ;
         RECT  775.635 0.0 776.015 0.38 ;
      END
   END dout0[74]
   PIN dout0[75]
      DIRECTION OUTPUT ;
      PORT
         LAYER met4 ;
         RECT  784.345 0.0 784.725 0.38 ;
      END
   END dout0[75]
   PIN dout0[76]
      DIRECTION OUTPUT ;
      PORT
         LAYER met4 ;
         RECT  789.81 0.0 790.19 0.38 ;
      END
   END dout0[76]
   PIN dout0[77]
      DIRECTION OUTPUT ;
      PORT
         LAYER met4 ;
         RECT  795.65 0.0 796.03 0.38 ;
      END
   END dout0[77]
   PIN dout0[78]
      DIRECTION OUTPUT ;
      PORT
         LAYER met4 ;
         RECT  801.685 0.0 802.065 0.38 ;
      END
   END dout0[78]
   PIN dout0[79]
      DIRECTION OUTPUT ;
      PORT
         LAYER met4 ;
         RECT  807.925 0.0 808.305 0.38 ;
      END
   END dout0[79]
   PIN dout0[80]
      DIRECTION OUTPUT ;
      PORT
         LAYER met4 ;
         RECT  814.165 0.0 814.545 0.38 ;
      END
   END dout0[80]
   PIN dout0[81]
      DIRECTION OUTPUT ;
      PORT
         LAYER met4 ;
         RECT  820.405 0.0 820.785 0.38 ;
      END
   END dout0[81]
   PIN dout0[82]
      DIRECTION OUTPUT ;
      PORT
         LAYER met4 ;
         RECT  826.645 0.0 827.025 0.38 ;
      END
   END dout0[82]
   PIN dout0[83]
      DIRECTION OUTPUT ;
      PORT
         LAYER met4 ;
         RECT  832.885 0.0 833.265 0.38 ;
      END
   END dout0[83]
   PIN dout0[84]
      DIRECTION OUTPUT ;
      PORT
         LAYER met4 ;
         RECT  839.125 0.0 839.505 0.38 ;
      END
   END dout0[84]
   PIN dout0[85]
      DIRECTION OUTPUT ;
      PORT
         LAYER met4 ;
         RECT  845.365 0.0 845.745 0.38 ;
      END
   END dout0[85]
   PIN dout0[86]
      DIRECTION OUTPUT ;
      PORT
         LAYER met4 ;
         RECT  851.555 0.0 851.935 0.38 ;
      END
   END dout0[86]
   PIN dout0[87]
      DIRECTION OUTPUT ;
      PORT
         LAYER met4 ;
         RECT  857.16 0.0 857.54 0.38 ;
      END
   END dout0[87]
   PIN dout0[88]
      DIRECTION OUTPUT ;
      PORT
         LAYER met4 ;
         RECT  863.235 0.0 863.615 0.38 ;
      END
   END dout0[88]
   PIN dout0[89]
      DIRECTION OUTPUT ;
      PORT
         LAYER met4 ;
         RECT  869.075 0.0 869.455 0.38 ;
      END
   END dout0[89]
   PIN dout0[90]
      DIRECTION OUTPUT ;
      PORT
         LAYER met4 ;
         RECT  877.945 0.0 878.325 0.38 ;
      END
   END dout0[90]
   PIN dout0[91]
      DIRECTION OUTPUT ;
      PORT
         LAYER met4 ;
         RECT  883.25 0.0 883.63 0.38 ;
      END
   END dout0[91]
   PIN dout0[92]
      DIRECTION OUTPUT ;
      PORT
         LAYER met4 ;
         RECT  889.105 0.0 889.485 0.38 ;
      END
   END dout0[92]
   PIN dout0[93]
      DIRECTION OUTPUT ;
      PORT
         LAYER met4 ;
         RECT  895.285 0.0 895.665 0.38 ;
      END
   END dout0[93]
   PIN dout0[94]
      DIRECTION OUTPUT ;
      PORT
         LAYER met4 ;
         RECT  901.525 0.0 901.905 0.38 ;
      END
   END dout0[94]
   PIN dout0[95]
      DIRECTION OUTPUT ;
      PORT
         LAYER met4 ;
         RECT  907.765 0.0 908.145 0.38 ;
      END
   END dout0[95]
   PIN dout0[96]
      DIRECTION OUTPUT ;
      PORT
         LAYER met4 ;
         RECT  914.005 0.0 914.385 0.38 ;
      END
   END dout0[96]
   PIN dout0[97]
      DIRECTION OUTPUT ;
      PORT
         LAYER met4 ;
         RECT  920.245 0.0 920.625 0.38 ;
      END
   END dout0[97]
   PIN dout0[98]
      DIRECTION OUTPUT ;
      PORT
         LAYER met4 ;
         RECT  926.485 0.0 926.865 0.38 ;
      END
   END dout0[98]
   PIN dout0[99]
      DIRECTION OUTPUT ;
      PORT
         LAYER met4 ;
         RECT  932.725 0.0 933.105 0.38 ;
      END
   END dout0[99]
   PIN dout0[100]
      DIRECTION OUTPUT ;
      PORT
         LAYER met4 ;
         RECT  938.965 0.0 939.345 0.38 ;
      END
   END dout0[100]
   PIN dout0[101]
      DIRECTION OUTPUT ;
      PORT
         LAYER met4 ;
         RECT  944.995 0.0 945.375 0.38 ;
      END
   END dout0[101]
   PIN dout0[102]
      DIRECTION OUTPUT ;
      PORT
         LAYER met4 ;
         RECT  950.76 0.0 951.14 0.38 ;
      END
   END dout0[102]
   PIN dout0[103]
      DIRECTION OUTPUT ;
      PORT
         LAYER met4 ;
         RECT  956.675 0.0 957.055 0.38 ;
      END
   END dout0[103]
   PIN dout0[104]
      DIRECTION OUTPUT ;
      PORT
         LAYER met4 ;
         RECT  965.305 0.0 965.685 0.38 ;
      END
   END dout0[104]
   PIN dout0[105]
      DIRECTION OUTPUT ;
      PORT
         LAYER met4 ;
         RECT  970.85 0.0 971.23 0.38 ;
      END
   END dout0[105]
   PIN dout0[106]
      DIRECTION OUTPUT ;
      PORT
         LAYER met4 ;
         RECT  976.69 0.0 977.07 0.38 ;
      END
   END dout0[106]
   PIN dout0[107]
      DIRECTION OUTPUT ;
      PORT
         LAYER met4 ;
         RECT  982.645 0.0 983.025 0.38 ;
      END
   END dout0[107]
   PIN dout0[108]
      DIRECTION OUTPUT ;
      PORT
         LAYER met4 ;
         RECT  988.885 0.0 989.265 0.38 ;
      END
   END dout0[108]
   PIN dout0[109]
      DIRECTION OUTPUT ;
      PORT
         LAYER met4 ;
         RECT  995.125 0.0 995.505 0.38 ;
      END
   END dout0[109]
   PIN dout0[110]
      DIRECTION OUTPUT ;
      PORT
         LAYER met4 ;
         RECT  1001.365 0.0 1001.745 0.38 ;
      END
   END dout0[110]
   PIN dout0[111]
      DIRECTION OUTPUT ;
      PORT
         LAYER met4 ;
         RECT  1007.605 0.0 1007.985 0.38 ;
      END
   END dout0[111]
   PIN dout0[112]
      DIRECTION OUTPUT ;
      PORT
         LAYER met4 ;
         RECT  1013.845 0.0 1014.225 0.38 ;
      END
   END dout0[112]
   PIN dout0[113]
      DIRECTION OUTPUT ;
      PORT
         LAYER met4 ;
         RECT  1020.085 0.0 1020.465 0.38 ;
      END
   END dout0[113]
   PIN dout0[114]
      DIRECTION OUTPUT ;
      PORT
         LAYER met4 ;
         RECT  1026.325 0.0 1026.705 0.38 ;
      END
   END dout0[114]
   PIN dout0[115]
      DIRECTION OUTPUT ;
      PORT
         LAYER met4 ;
         RECT  1032.565 0.0 1032.945 0.38 ;
      END
   END dout0[115]
   PIN dout0[116]
      DIRECTION OUTPUT ;
      PORT
         LAYER met4 ;
         RECT  1038.435 0.0 1038.815 0.38 ;
      END
   END dout0[116]
   PIN dout0[117]
      DIRECTION OUTPUT ;
      PORT
         LAYER met4 ;
         RECT  1044.275 0.0 1044.655 0.38 ;
      END
   END dout0[117]
   PIN dout0[118]
      DIRECTION OUTPUT ;
      PORT
         LAYER met4 ;
         RECT  1050.115 0.0 1050.495 0.38 ;
      END
   END dout0[118]
   PIN dout0[119]
      DIRECTION OUTPUT ;
      PORT
         LAYER met4 ;
         RECT  1058.905 0.0 1059.285 0.38 ;
      END
   END dout0[119]
   PIN dout0[120]
      DIRECTION OUTPUT ;
      PORT
         LAYER met4 ;
         RECT  1064.29 0.0 1064.67 0.38 ;
      END
   END dout0[120]
   PIN dout0[121]
      DIRECTION OUTPUT ;
      PORT
         LAYER met4 ;
         RECT  1070.13 0.0 1070.51 0.38 ;
      END
   END dout0[121]
   PIN dout0[122]
      DIRECTION OUTPUT ;
      PORT
         LAYER met4 ;
         RECT  1076.245 0.0 1076.625 0.38 ;
      END
   END dout0[122]
   PIN dout0[123]
      DIRECTION OUTPUT ;
      PORT
         LAYER met4 ;
         RECT  1082.485 0.0 1082.865 0.38 ;
      END
   END dout0[123]
   PIN dout0[124]
      DIRECTION OUTPUT ;
      PORT
         LAYER met4 ;
         RECT  1088.725 0.0 1089.105 0.38 ;
      END
   END dout0[124]
   PIN dout0[125]
      DIRECTION OUTPUT ;
      PORT
         LAYER met4 ;
         RECT  1094.965 0.0 1095.345 0.38 ;
      END
   END dout0[125]
   PIN dout0[126]
      DIRECTION OUTPUT ;
      PORT
         LAYER met4 ;
         RECT  1101.205 0.0 1101.585 0.38 ;
      END
   END dout0[126]
   PIN dout0[127]
      DIRECTION OUTPUT ;
      PORT
         LAYER met4 ;
         RECT  1107.445 0.0 1107.825 0.38 ;
      END
   END dout0[127]
   PIN dout0[128]
      DIRECTION OUTPUT ;
      PORT
         LAYER met4 ;
         RECT  1113.685 0.0 1114.065 0.38 ;
      END
   END dout0[128]
   PIN dout0[129]
      DIRECTION OUTPUT ;
      PORT
         LAYER met4 ;
         RECT  1119.925 0.0 1120.305 0.38 ;
      END
   END dout0[129]
   PIN dout0[130]
      DIRECTION OUTPUT ;
      PORT
         LAYER met4 ;
         RECT  1126.035 0.0 1126.415 0.38 ;
      END
   END dout0[130]
   PIN dout0[131]
      DIRECTION OUTPUT ;
      PORT
         LAYER met4 ;
         RECT  1131.72 0.0 1132.1 0.38 ;
      END
   END dout0[131]
   PIN dout0[132]
      DIRECTION OUTPUT ;
      PORT
         LAYER met4 ;
         RECT  1137.715 0.0 1138.095 0.38 ;
      END
   END dout0[132]
   PIN dout0[133]
      DIRECTION OUTPUT ;
      PORT
         LAYER met4 ;
         RECT  1146.265 0.0 1146.645 0.38 ;
      END
   END dout0[133]
   PIN dout0[134]
      DIRECTION OUTPUT ;
      PORT
         LAYER met4 ;
         RECT  1151.89 0.0 1152.27 0.38 ;
      END
   END dout0[134]
   PIN dout0[135]
      DIRECTION OUTPUT ;
      PORT
         LAYER met4 ;
         RECT  1157.73 0.0 1158.11 0.38 ;
      END
   END dout0[135]
   PIN dout0[136]
      DIRECTION OUTPUT ;
      PORT
         LAYER met4 ;
         RECT  1163.605 0.0 1163.985 0.38 ;
      END
   END dout0[136]
   PIN dout0[137]
      DIRECTION OUTPUT ;
      PORT
         LAYER met4 ;
         RECT  1169.845 0.0 1170.225 0.38 ;
      END
   END dout0[137]
   PIN dout0[138]
      DIRECTION OUTPUT ;
      PORT
         LAYER met4 ;
         RECT  1176.085 0.0 1176.465 0.38 ;
      END
   END dout0[138]
   PIN dout0[139]
      DIRECTION OUTPUT ;
      PORT
         LAYER met4 ;
         RECT  1182.325 0.0 1182.705 0.38 ;
      END
   END dout0[139]
   PIN dout0[140]
      DIRECTION OUTPUT ;
      PORT
         LAYER met4 ;
         RECT  1188.565 0.0 1188.945 0.38 ;
      END
   END dout0[140]
   PIN dout0[141]
      DIRECTION OUTPUT ;
      PORT
         LAYER met4 ;
         RECT  1194.805 0.0 1195.185 0.38 ;
      END
   END dout0[141]
   PIN dout0[142]
      DIRECTION OUTPUT ;
      PORT
         LAYER met4 ;
         RECT  1201.045 0.0 1201.425 0.38 ;
      END
   END dout0[142]
   PIN dout0[143]
      DIRECTION OUTPUT ;
      PORT
         LAYER met4 ;
         RECT  1207.285 0.0 1207.665 0.38 ;
      END
   END dout0[143]
   PIN dout0[144]
      DIRECTION OUTPUT ;
      PORT
         LAYER met4 ;
         RECT  1213.525 0.0 1213.905 0.38 ;
      END
   END dout0[144]
   PIN dout0[145]
      DIRECTION OUTPUT ;
      PORT
         LAYER met4 ;
         RECT  1219.475 0.0 1219.855 0.38 ;
      END
   END dout0[145]
   PIN dout0[146]
      DIRECTION OUTPUT ;
      PORT
         LAYER met4 ;
         RECT  1225.315 0.0 1225.695 0.38 ;
      END
   END dout0[146]
   PIN dout0[147]
      DIRECTION OUTPUT ;
      PORT
         LAYER met4 ;
         RECT  1231.155 0.0 1231.535 0.38 ;
      END
   END dout0[147]
   PIN dout0[148]
      DIRECTION OUTPUT ;
      PORT
         LAYER met4 ;
         RECT  1239.865 0.0 1240.245 0.38 ;
      END
   END dout0[148]
   PIN dout0[149]
      DIRECTION OUTPUT ;
      PORT
         LAYER met4 ;
         RECT  1245.33 0.0 1245.71 0.38 ;
      END
   END dout0[149]
   PIN dout0[150]
      DIRECTION OUTPUT ;
      PORT
         LAYER met4 ;
         RECT  1251.17 0.0 1251.55 0.38 ;
      END
   END dout0[150]
   PIN dout0[151]
      DIRECTION OUTPUT ;
      PORT
         LAYER met4 ;
         RECT  1257.205 0.0 1257.585 0.38 ;
      END
   END dout0[151]
   PIN dout0[152]
      DIRECTION OUTPUT ;
      PORT
         LAYER met4 ;
         RECT  1263.445 0.0 1263.825 0.38 ;
      END
   END dout0[152]
   PIN dout0[153]
      DIRECTION OUTPUT ;
      PORT
         LAYER met4 ;
         RECT  1269.685 0.0 1270.065 0.38 ;
      END
   END dout0[153]
   PIN dout0[154]
      DIRECTION OUTPUT ;
      PORT
         LAYER met4 ;
         RECT  1275.925 0.0 1276.305 0.38 ;
      END
   END dout0[154]
   PIN dout0[155]
      DIRECTION OUTPUT ;
      PORT
         LAYER met4 ;
         RECT  1282.165 0.0 1282.545 0.38 ;
      END
   END dout0[155]
   PIN dout0[156]
      DIRECTION OUTPUT ;
      PORT
         LAYER met4 ;
         RECT  1288.405 0.0 1288.785 0.38 ;
      END
   END dout0[156]
   PIN dout0[157]
      DIRECTION OUTPUT ;
      PORT
         LAYER met4 ;
         RECT  1294.645 0.0 1295.025 0.38 ;
      END
   END dout0[157]
   PIN dout0[158]
      DIRECTION OUTPUT ;
      PORT
         LAYER met4 ;
         RECT  1300.885 0.0 1301.265 0.38 ;
      END
   END dout0[158]
   PIN dout0[159]
      DIRECTION OUTPUT ;
      PORT
         LAYER met4 ;
         RECT  1307.075 0.0 1307.455 0.38 ;
      END
   END dout0[159]
   PIN dout0[160]
      DIRECTION OUTPUT ;
      PORT
         LAYER met4 ;
         RECT  1312.68 0.0 1313.06 0.38 ;
      END
   END dout0[160]
   PIN dout0[161]
      DIRECTION OUTPUT ;
      PORT
         LAYER met4 ;
         RECT  1318.755 0.0 1319.135 0.38 ;
      END
   END dout0[161]
   PIN dout0[162]
      DIRECTION OUTPUT ;
      PORT
         LAYER met4 ;
         RECT  1324.595 0.0 1324.975 0.38 ;
      END
   END dout0[162]
   PIN dout0[163]
      DIRECTION OUTPUT ;
      PORT
         LAYER met4 ;
         RECT  1333.465 0.0 1333.845 0.38 ;
      END
   END dout0[163]
   PIN dout0[164]
      DIRECTION OUTPUT ;
      PORT
         LAYER met4 ;
         RECT  1338.77 0.0 1339.15 0.38 ;
      END
   END dout0[164]
   PIN dout0[165]
      DIRECTION OUTPUT ;
      PORT
         LAYER met4 ;
         RECT  1344.625 0.0 1345.005 0.38 ;
      END
   END dout0[165]
   PIN dout0[166]
      DIRECTION OUTPUT ;
      PORT
         LAYER met4 ;
         RECT  1350.805 0.0 1351.185 0.38 ;
      END
   END dout0[166]
   PIN dout0[167]
      DIRECTION OUTPUT ;
      PORT
         LAYER met4 ;
         RECT  1357.045 0.0 1357.425 0.38 ;
      END
   END dout0[167]
   PIN dout0[168]
      DIRECTION OUTPUT ;
      PORT
         LAYER met4 ;
         RECT  1363.285 0.0 1363.665 0.38 ;
      END
   END dout0[168]
   PIN dout0[169]
      DIRECTION OUTPUT ;
      PORT
         LAYER met4 ;
         RECT  1369.525 0.0 1369.905 0.38 ;
      END
   END dout0[169]
   PIN dout0[170]
      DIRECTION OUTPUT ;
      PORT
         LAYER met4 ;
         RECT  1375.765 0.0 1376.145 0.38 ;
      END
   END dout0[170]
   PIN dout0[171]
      DIRECTION OUTPUT ;
      PORT
         LAYER met4 ;
         RECT  1382.005 0.0 1382.385 0.38 ;
      END
   END dout0[171]
   PIN dout0[172]
      DIRECTION OUTPUT ;
      PORT
         LAYER met4 ;
         RECT  1388.245 0.0 1388.625 0.38 ;
      END
   END dout0[172]
   PIN dout0[173]
      DIRECTION OUTPUT ;
      PORT
         LAYER met4 ;
         RECT  1394.485 0.0 1394.865 0.38 ;
      END
   END dout0[173]
   PIN dout0[174]
      DIRECTION OUTPUT ;
      PORT
         LAYER met4 ;
         RECT  1400.515 0.0 1400.895 0.38 ;
      END
   END dout0[174]
   PIN dout0[175]
      DIRECTION OUTPUT ;
      PORT
         LAYER met4 ;
         RECT  1406.28 0.0 1406.66 0.38 ;
      END
   END dout0[175]
   PIN dout0[176]
      DIRECTION OUTPUT ;
      PORT
         LAYER met4 ;
         RECT  1412.195 0.0 1412.575 0.38 ;
      END
   END dout0[176]
   PIN dout0[177]
      DIRECTION OUTPUT ;
      PORT
         LAYER met4 ;
         RECT  1420.825 0.0 1421.205 0.38 ;
      END
   END dout0[177]
   PIN dout0[178]
      DIRECTION OUTPUT ;
      PORT
         LAYER met4 ;
         RECT  1426.37 0.0 1426.75 0.38 ;
      END
   END dout0[178]
   PIN dout0[179]
      DIRECTION OUTPUT ;
      PORT
         LAYER met4 ;
         RECT  1432.21 0.0 1432.59 0.38 ;
      END
   END dout0[179]
   PIN dout0[180]
      DIRECTION OUTPUT ;
      PORT
         LAYER met4 ;
         RECT  1438.165 0.0 1438.545 0.38 ;
      END
   END dout0[180]
   PIN dout0[181]
      DIRECTION OUTPUT ;
      PORT
         LAYER met4 ;
         RECT  1444.405 0.0 1444.785 0.38 ;
      END
   END dout0[181]
   PIN dout0[182]
      DIRECTION OUTPUT ;
      PORT
         LAYER met4 ;
         RECT  1450.645 0.0 1451.025 0.38 ;
      END
   END dout0[182]
   PIN dout0[183]
      DIRECTION OUTPUT ;
      PORT
         LAYER met4 ;
         RECT  1456.885 0.0 1457.265 0.38 ;
      END
   END dout0[183]
   PIN dout0[184]
      DIRECTION OUTPUT ;
      PORT
         LAYER met4 ;
         RECT  1463.125 0.0 1463.505 0.38 ;
      END
   END dout0[184]
   PIN dout0[185]
      DIRECTION OUTPUT ;
      PORT
         LAYER met4 ;
         RECT  1469.365 0.0 1469.745 0.38 ;
      END
   END dout0[185]
   PIN dout0[186]
      DIRECTION OUTPUT ;
      PORT
         LAYER met4 ;
         RECT  1475.605 0.0 1475.985 0.38 ;
      END
   END dout0[186]
   PIN dout0[187]
      DIRECTION OUTPUT ;
      PORT
         LAYER met4 ;
         RECT  1481.845 0.0 1482.225 0.38 ;
      END
   END dout0[187]
   PIN dout0[188]
      DIRECTION OUTPUT ;
      PORT
         LAYER met4 ;
         RECT  1488.085 0.0 1488.465 0.38 ;
      END
   END dout0[188]
   PIN dout0[189]
      DIRECTION OUTPUT ;
      PORT
         LAYER met4 ;
         RECT  1493.955 0.0 1494.335 0.38 ;
      END
   END dout0[189]
   PIN dout0[190]
      DIRECTION OUTPUT ;
      PORT
         LAYER met4 ;
         RECT  1499.795 0.0 1500.175 0.38 ;
      END
   END dout0[190]
   PIN dout0[191]
      DIRECTION OUTPUT ;
      PORT
         LAYER met4 ;
         RECT  1505.635 0.0 1506.015 0.38 ;
      END
   END dout0[191]
   PIN dout0[192]
      DIRECTION OUTPUT ;
      PORT
         LAYER met4 ;
         RECT  1514.425 0.0 1514.805 0.38 ;
      END
   END dout0[192]
   PIN dout0[193]
      DIRECTION OUTPUT ;
      PORT
         LAYER met4 ;
         RECT  1519.81 0.0 1520.19 0.38 ;
      END
   END dout0[193]
   PIN dout0[194]
      DIRECTION OUTPUT ;
      PORT
         LAYER met4 ;
         RECT  1525.65 0.0 1526.03 0.38 ;
      END
   END dout0[194]
   PIN dout0[195]
      DIRECTION OUTPUT ;
      PORT
         LAYER met4 ;
         RECT  1531.765 0.0 1532.145 0.38 ;
      END
   END dout0[195]
   PIN dout0[196]
      DIRECTION OUTPUT ;
      PORT
         LAYER met4 ;
         RECT  1538.005 0.0 1538.385 0.38 ;
      END
   END dout0[196]
   PIN dout0[197]
      DIRECTION OUTPUT ;
      PORT
         LAYER met4 ;
         RECT  1544.245 0.0 1544.625 0.38 ;
      END
   END dout0[197]
   PIN dout0[198]
      DIRECTION OUTPUT ;
      PORT
         LAYER met4 ;
         RECT  1550.485 0.0 1550.865 0.38 ;
      END
   END dout0[198]
   PIN dout0[199]
      DIRECTION OUTPUT ;
      PORT
         LAYER met4 ;
         RECT  1556.725 0.0 1557.105 0.38 ;
      END
   END dout0[199]
   PIN dout0[200]
      DIRECTION OUTPUT ;
      PORT
         LAYER met4 ;
         RECT  1562.965 0.0 1563.345 0.38 ;
      END
   END dout0[200]
   PIN dout0[201]
      DIRECTION OUTPUT ;
      PORT
         LAYER met4 ;
         RECT  1569.205 0.0 1569.585 0.38 ;
      END
   END dout0[201]
   PIN dout0[202]
      DIRECTION OUTPUT ;
      PORT
         LAYER met4 ;
         RECT  1575.445 0.0 1575.825 0.38 ;
      END
   END dout0[202]
   PIN dout0[203]
      DIRECTION OUTPUT ;
      PORT
         LAYER met4 ;
         RECT  1581.555 0.0 1581.935 0.38 ;
      END
   END dout0[203]
   PIN dout0[204]
      DIRECTION OUTPUT ;
      PORT
         LAYER met4 ;
         RECT  1587.24 0.0 1587.62 0.38 ;
      END
   END dout0[204]
   PIN dout0[205]
      DIRECTION OUTPUT ;
      PORT
         LAYER met4 ;
         RECT  1593.235 0.0 1593.615 0.38 ;
      END
   END dout0[205]
   PIN dout0[206]
      DIRECTION OUTPUT ;
      PORT
         LAYER met4 ;
         RECT  1601.785 0.0 1602.165 0.38 ;
      END
   END dout0[206]
   PIN dout0[207]
      DIRECTION OUTPUT ;
      PORT
         LAYER met4 ;
         RECT  1607.41 0.0 1607.79 0.38 ;
      END
   END dout0[207]
   PIN dout0[208]
      DIRECTION OUTPUT ;
      PORT
         LAYER met4 ;
         RECT  1613.25 0.0 1613.63 0.38 ;
      END
   END dout0[208]
   PIN dout0[209]
      DIRECTION OUTPUT ;
      PORT
         LAYER met4 ;
         RECT  1619.125 0.0 1619.505 0.38 ;
      END
   END dout0[209]
   PIN dout0[210]
      DIRECTION OUTPUT ;
      PORT
         LAYER met4 ;
         RECT  1625.365 0.0 1625.745 0.38 ;
      END
   END dout0[210]
   PIN dout0[211]
      DIRECTION OUTPUT ;
      PORT
         LAYER met4 ;
         RECT  1631.605 0.0 1631.985 0.38 ;
      END
   END dout0[211]
   PIN dout0[212]
      DIRECTION OUTPUT ;
      PORT
         LAYER met4 ;
         RECT  1637.845 0.0 1638.225 0.38 ;
      END
   END dout0[212]
   PIN dout0[213]
      DIRECTION OUTPUT ;
      PORT
         LAYER met4 ;
         RECT  1644.085 0.0 1644.465 0.38 ;
      END
   END dout0[213]
   PIN dout0[214]
      DIRECTION OUTPUT ;
      PORT
         LAYER met4 ;
         RECT  1650.325 0.0 1650.705 0.38 ;
      END
   END dout0[214]
   PIN dout0[215]
      DIRECTION OUTPUT ;
      PORT
         LAYER met4 ;
         RECT  1656.565 0.0 1656.945 0.38 ;
      END
   END dout0[215]
   PIN dout0[216]
      DIRECTION OUTPUT ;
      PORT
         LAYER met4 ;
         RECT  1662.805 0.0 1663.185 0.38 ;
      END
   END dout0[216]
   PIN dout0[217]
      DIRECTION OUTPUT ;
      PORT
         LAYER met4 ;
         RECT  1669.045 0.0 1669.425 0.38 ;
      END
   END dout0[217]
   PIN dout0[218]
      DIRECTION OUTPUT ;
      PORT
         LAYER met4 ;
         RECT  1674.995 0.0 1675.375 0.38 ;
      END
   END dout0[218]
   PIN dout0[219]
      DIRECTION OUTPUT ;
      PORT
         LAYER met4 ;
         RECT  1680.835 0.0 1681.215 0.38 ;
      END
   END dout0[219]
   PIN dout0[220]
      DIRECTION OUTPUT ;
      PORT
         LAYER met4 ;
         RECT  1686.675 0.0 1687.055 0.38 ;
      END
   END dout0[220]
   PIN dout0[221]
      DIRECTION OUTPUT ;
      PORT
         LAYER met4 ;
         RECT  1695.385 0.0 1695.765 0.38 ;
      END
   END dout0[221]
   PIN dout0[222]
      DIRECTION OUTPUT ;
      PORT
         LAYER met4 ;
         RECT  1700.85 0.0 1701.23 0.38 ;
      END
   END dout0[222]
   PIN dout0[223]
      DIRECTION OUTPUT ;
      PORT
         LAYER met4 ;
         RECT  1706.69 0.0 1707.07 0.38 ;
      END
   END dout0[223]
   PIN dout0[224]
      DIRECTION OUTPUT ;
      PORT
         LAYER met4 ;
         RECT  1712.725 0.0 1713.105 0.38 ;
      END
   END dout0[224]
   PIN dout0[225]
      DIRECTION OUTPUT ;
      PORT
         LAYER met4 ;
         RECT  1718.965 0.0 1719.345 0.38 ;
      END
   END dout0[225]
   PIN dout0[226]
      DIRECTION OUTPUT ;
      PORT
         LAYER met4 ;
         RECT  1725.205 0.0 1725.585 0.38 ;
      END
   END dout0[226]
   PIN dout0[227]
      DIRECTION OUTPUT ;
      PORT
         LAYER met4 ;
         RECT  1731.445 0.0 1731.825 0.38 ;
      END
   END dout0[227]
   PIN dout0[228]
      DIRECTION OUTPUT ;
      PORT
         LAYER met4 ;
         RECT  1737.685 0.0 1738.065 0.38 ;
      END
   END dout0[228]
   PIN dout0[229]
      DIRECTION OUTPUT ;
      PORT
         LAYER met4 ;
         RECT  1743.925 0.0 1744.305 0.38 ;
      END
   END dout0[229]
   PIN dout0[230]
      DIRECTION OUTPUT ;
      PORT
         LAYER met4 ;
         RECT  1750.165 0.0 1750.545 0.38 ;
      END
   END dout0[230]
   PIN dout0[231]
      DIRECTION OUTPUT ;
      PORT
         LAYER met4 ;
         RECT  1756.405 0.0 1756.785 0.38 ;
      END
   END dout0[231]
   PIN dout0[232]
      DIRECTION OUTPUT ;
      PORT
         LAYER met4 ;
         RECT  1762.595 0.0 1762.975 0.38 ;
      END
   END dout0[232]
   PIN dout0[233]
      DIRECTION OUTPUT ;
      PORT
         LAYER met4 ;
         RECT  1768.885 0.0 1769.265 0.38 ;
      END
   END dout0[233]
   PIN dout0[234]
      DIRECTION OUTPUT ;
      PORT
         LAYER met4 ;
         RECT  1775.125 0.0 1775.505 0.38 ;
      END
   END dout0[234]
   PIN dout0[235]
      DIRECTION OUTPUT ;
      PORT
         LAYER met4 ;
         RECT  1781.365 0.0 1781.745 0.38 ;
      END
   END dout0[235]
   PIN dout0[236]
      DIRECTION OUTPUT ;
      PORT
         LAYER met4 ;
         RECT  1787.605 0.0 1787.985 0.38 ;
      END
   END dout0[236]
   PIN dout0[237]
      DIRECTION OUTPUT ;
      PORT
         LAYER met4 ;
         RECT  1793.845 0.0 1794.225 0.38 ;
      END
   END dout0[237]
   PIN dout0[238]
      DIRECTION OUTPUT ;
      PORT
         LAYER met4 ;
         RECT  1800.085 0.0 1800.465 0.38 ;
      END
   END dout0[238]
   PIN dout0[239]
      DIRECTION OUTPUT ;
      PORT
         LAYER met4 ;
         RECT  1806.325 0.0 1806.705 0.38 ;
      END
   END dout0[239]
   PIN dout0[240]
      DIRECTION OUTPUT ;
      PORT
         LAYER met4 ;
         RECT  1812.565 0.0 1812.945 0.38 ;
      END
   END dout0[240]
   PIN dout0[241]
      DIRECTION OUTPUT ;
      PORT
         LAYER met4 ;
         RECT  1818.805 0.0 1819.185 0.38 ;
      END
   END dout0[241]
   PIN dout0[242]
      DIRECTION OUTPUT ;
      PORT
         LAYER met4 ;
         RECT  1825.045 0.0 1825.425 0.38 ;
      END
   END dout0[242]
   PIN dout0[243]
      DIRECTION OUTPUT ;
      PORT
         LAYER met4 ;
         RECT  1831.285 0.0 1831.665 0.38 ;
      END
   END dout0[243]
   PIN dout0[244]
      DIRECTION OUTPUT ;
      PORT
         LAYER met4 ;
         RECT  1837.525 0.0 1837.905 0.38 ;
      END
   END dout0[244]
   PIN dout0[245]
      DIRECTION OUTPUT ;
      PORT
         LAYER met4 ;
         RECT  1843.765 0.0 1844.145 0.38 ;
      END
   END dout0[245]
   PIN dout0[246]
      DIRECTION OUTPUT ;
      PORT
         LAYER met4 ;
         RECT  1850.005 0.0 1850.385 0.38 ;
      END
   END dout0[246]
   PIN dout0[247]
      DIRECTION OUTPUT ;
      PORT
         LAYER met4 ;
         RECT  1856.245 0.0 1856.625 0.38 ;
      END
   END dout0[247]
   PIN dout0[248]
      DIRECTION OUTPUT ;
      PORT
         LAYER met4 ;
         RECT  1862.485 0.0 1862.865 0.38 ;
      END
   END dout0[248]
   PIN dout0[249]
      DIRECTION OUTPUT ;
      PORT
         LAYER met4 ;
         RECT  1868.725 0.0 1869.105 0.38 ;
      END
   END dout0[249]
   PIN dout0[250]
      DIRECTION OUTPUT ;
      PORT
         LAYER met4 ;
         RECT  1874.965 0.0 1875.345 0.38 ;
      END
   END dout0[250]
   PIN dout0[251]
      DIRECTION OUTPUT ;
      PORT
         LAYER met4 ;
         RECT  1881.205 0.0 1881.585 0.38 ;
      END
   END dout0[251]
   PIN dout0[252]
      DIRECTION OUTPUT ;
      PORT
         LAYER met4 ;
         RECT  1887.445 0.0 1887.825 0.38 ;
      END
   END dout0[252]
   PIN dout0[253]
      DIRECTION OUTPUT ;
      PORT
         LAYER met4 ;
         RECT  1893.685 0.0 1894.065 0.38 ;
      END
   END dout0[253]
   PIN dout0[254]
      DIRECTION OUTPUT ;
      PORT
         LAYER met4 ;
         RECT  1899.925 0.0 1900.305 0.38 ;
      END
   END dout0[254]
   PIN dout0[255]
      DIRECTION OUTPUT ;
      PORT
         LAYER met4 ;
         RECT  1906.165 0.0 1906.545 0.38 ;
      END
   END dout0[255]
   PIN dout0[256]
      DIRECTION OUTPUT ;
      PORT
         LAYER met4 ;
         RECT  1912.405 0.0 1912.785 0.38 ;
      END
   END dout0[256]
   PIN dout1[0]
      DIRECTION OUTPUT ;
      PORT
         LAYER met4 ;
         RECT  315.025 226.055 315.405 226.435 ;
      END
   END dout1[0]
   PIN dout1[1]
      DIRECTION OUTPUT ;
      PORT
         LAYER met4 ;
         RECT  321.265 226.055 321.645 226.435 ;
      END
   END dout1[1]
   PIN dout1[2]
      DIRECTION OUTPUT ;
      PORT
         LAYER met4 ;
         RECT  327.505 226.055 327.885 226.435 ;
      END
   END dout1[2]
   PIN dout1[3]
      DIRECTION OUTPUT ;
      PORT
         LAYER met4 ;
         RECT  333.745 226.055 334.125 226.435 ;
      END
   END dout1[3]
   PIN dout1[4]
      DIRECTION OUTPUT ;
      PORT
         LAYER met4 ;
         RECT  339.985 226.055 340.365 226.435 ;
      END
   END dout1[4]
   PIN dout1[5]
      DIRECTION OUTPUT ;
      PORT
         LAYER met4 ;
         RECT  346.225 226.055 346.605 226.435 ;
      END
   END dout1[5]
   PIN dout1[6]
      DIRECTION OUTPUT ;
      PORT
         LAYER met4 ;
         RECT  352.465 226.055 352.845 226.435 ;
      END
   END dout1[6]
   PIN dout1[7]
      DIRECTION OUTPUT ;
      PORT
         LAYER met4 ;
         RECT  358.705 226.055 359.085 226.435 ;
      END
   END dout1[7]
   PIN dout1[8]
      DIRECTION OUTPUT ;
      PORT
         LAYER met4 ;
         RECT  364.945 226.055 365.325 226.435 ;
      END
   END dout1[8]
   PIN dout1[9]
      DIRECTION OUTPUT ;
      PORT
         LAYER met4 ;
         RECT  371.185 226.055 371.565 226.435 ;
      END
   END dout1[9]
   PIN dout1[10]
      DIRECTION OUTPUT ;
      PORT
         LAYER met4 ;
         RECT  377.425 226.055 377.805 226.435 ;
      END
   END dout1[10]
   PIN dout1[11]
      DIRECTION OUTPUT ;
      PORT
         LAYER met4 ;
         RECT  383.665 226.055 384.045 226.435 ;
      END
   END dout1[11]
   PIN dout1[12]
      DIRECTION OUTPUT ;
      PORT
         LAYER met4 ;
         RECT  389.905 226.055 390.285 226.435 ;
      END
   END dout1[12]
   PIN dout1[13]
      DIRECTION OUTPUT ;
      PORT
         LAYER met4 ;
         RECT  396.145 226.055 396.525 226.435 ;
      END
   END dout1[13]
   PIN dout1[14]
      DIRECTION OUTPUT ;
      PORT
         LAYER met4 ;
         RECT  402.385 226.055 402.765 226.435 ;
      END
   END dout1[14]
   PIN dout1[15]
      DIRECTION OUTPUT ;
      PORT
         LAYER met4 ;
         RECT  408.625 226.055 409.005 226.435 ;
      END
   END dout1[15]
   PIN dout1[16]
      DIRECTION OUTPUT ;
      PORT
         LAYER met4 ;
         RECT  414.865 226.055 415.245 226.435 ;
      END
   END dout1[16]
   PIN dout1[17]
      DIRECTION OUTPUT ;
      PORT
         LAYER met4 ;
         RECT  421.105 226.055 421.485 226.435 ;
      END
   END dout1[17]
   PIN dout1[18]
      DIRECTION OUTPUT ;
      PORT
         LAYER met4 ;
         RECT  427.345 226.055 427.725 226.435 ;
      END
   END dout1[18]
   PIN dout1[19]
      DIRECTION OUTPUT ;
      PORT
         LAYER met4 ;
         RECT  433.585 226.055 433.965 226.435 ;
      END
   END dout1[19]
   PIN dout1[20]
      DIRECTION OUTPUT ;
      PORT
         LAYER met4 ;
         RECT  439.825 226.055 440.205 226.435 ;
      END
   END dout1[20]
   PIN dout1[21]
      DIRECTION OUTPUT ;
      PORT
         LAYER met4 ;
         RECT  446.065 226.055 446.445 226.435 ;
      END
   END dout1[21]
   PIN dout1[22]
      DIRECTION OUTPUT ;
      PORT
         LAYER met4 ;
         RECT  452.305 226.055 452.685 226.435 ;
      END
   END dout1[22]
   PIN dout1[23]
      DIRECTION OUTPUT ;
      PORT
         LAYER met4 ;
         RECT  458.545 226.055 458.925 226.435 ;
      END
   END dout1[23]
   PIN dout1[24]
      DIRECTION OUTPUT ;
      PORT
         LAYER met4 ;
         RECT  464.785 226.055 465.165 226.435 ;
      END
   END dout1[24]
   PIN dout1[25]
      DIRECTION OUTPUT ;
      PORT
         LAYER met4 ;
         RECT  471.025 226.055 471.405 226.435 ;
      END
   END dout1[25]
   PIN dout1[26]
      DIRECTION OUTPUT ;
      PORT
         LAYER met4 ;
         RECT  477.265 226.055 477.645 226.435 ;
      END
   END dout1[26]
   PIN dout1[27]
      DIRECTION OUTPUT ;
      PORT
         LAYER met4 ;
         RECT  483.505 226.055 483.885 226.435 ;
      END
   END dout1[27]
   PIN dout1[28]
      DIRECTION OUTPUT ;
      PORT
         LAYER met4 ;
         RECT  489.745 226.055 490.125 226.435 ;
      END
   END dout1[28]
   PIN dout1[29]
      DIRECTION OUTPUT ;
      PORT
         LAYER met4 ;
         RECT  495.985 226.055 496.365 226.435 ;
      END
   END dout1[29]
   PIN dout1[30]
      DIRECTION OUTPUT ;
      PORT
         LAYER met4 ;
         RECT  502.225 226.055 502.605 226.435 ;
      END
   END dout1[30]
   PIN dout1[31]
      DIRECTION OUTPUT ;
      PORT
         LAYER met4 ;
         RECT  508.465 226.055 508.845 226.435 ;
      END
   END dout1[31]
   PIN dout1[32]
      DIRECTION OUTPUT ;
      PORT
         LAYER met4 ;
         RECT  514.705 226.055 515.085 226.435 ;
      END
   END dout1[32]
   PIN dout1[33]
      DIRECTION OUTPUT ;
      PORT
         LAYER met4 ;
         RECT  520.945 226.055 521.325 226.435 ;
      END
   END dout1[33]
   PIN dout1[34]
      DIRECTION OUTPUT ;
      PORT
         LAYER met4 ;
         RECT  527.185 226.055 527.565 226.435 ;
      END
   END dout1[34]
   PIN dout1[35]
      DIRECTION OUTPUT ;
      PORT
         LAYER met4 ;
         RECT  533.425 226.055 533.805 226.435 ;
      END
   END dout1[35]
   PIN dout1[36]
      DIRECTION OUTPUT ;
      PORT
         LAYER met4 ;
         RECT  539.665 226.055 540.045 226.435 ;
      END
   END dout1[36]
   PIN dout1[37]
      DIRECTION OUTPUT ;
      PORT
         LAYER met4 ;
         RECT  545.905 226.055 546.285 226.435 ;
      END
   END dout1[37]
   PIN dout1[38]
      DIRECTION OUTPUT ;
      PORT
         LAYER met4 ;
         RECT  552.145 226.055 552.525 226.435 ;
      END
   END dout1[38]
   PIN dout1[39]
      DIRECTION OUTPUT ;
      PORT
         LAYER met4 ;
         RECT  558.385 226.055 558.765 226.435 ;
      END
   END dout1[39]
   PIN dout1[40]
      DIRECTION OUTPUT ;
      PORT
         LAYER met4 ;
         RECT  564.625 226.055 565.005 226.435 ;
      END
   END dout1[40]
   PIN dout1[41]
      DIRECTION OUTPUT ;
      PORT
         LAYER met4 ;
         RECT  570.865 226.055 571.245 226.435 ;
      END
   END dout1[41]
   PIN dout1[42]
      DIRECTION OUTPUT ;
      PORT
         LAYER met4 ;
         RECT  577.105 226.055 577.485 226.435 ;
      END
   END dout1[42]
   PIN dout1[43]
      DIRECTION OUTPUT ;
      PORT
         LAYER met4 ;
         RECT  583.345 226.055 583.725 226.435 ;
      END
   END dout1[43]
   PIN dout1[44]
      DIRECTION OUTPUT ;
      PORT
         LAYER met4 ;
         RECT  589.585 226.055 589.965 226.435 ;
      END
   END dout1[44]
   PIN dout1[45]
      DIRECTION OUTPUT ;
      PORT
         LAYER met4 ;
         RECT  595.825 226.055 596.205 226.435 ;
      END
   END dout1[45]
   PIN dout1[46]
      DIRECTION OUTPUT ;
      PORT
         LAYER met4 ;
         RECT  602.065 226.055 602.445 226.435 ;
      END
   END dout1[46]
   PIN dout1[47]
      DIRECTION OUTPUT ;
      PORT
         LAYER met4 ;
         RECT  608.305 226.055 608.685 226.435 ;
      END
   END dout1[47]
   PIN dout1[48]
      DIRECTION OUTPUT ;
      PORT
         LAYER met4 ;
         RECT  614.545 226.055 614.925 226.435 ;
      END
   END dout1[48]
   PIN dout1[49]
      DIRECTION OUTPUT ;
      PORT
         LAYER met4 ;
         RECT  620.785 226.055 621.165 226.435 ;
      END
   END dout1[49]
   PIN dout1[50]
      DIRECTION OUTPUT ;
      PORT
         LAYER met4 ;
         RECT  627.025 226.055 627.405 226.435 ;
      END
   END dout1[50]
   PIN dout1[51]
      DIRECTION OUTPUT ;
      PORT
         LAYER met4 ;
         RECT  633.265 226.055 633.645 226.435 ;
      END
   END dout1[51]
   PIN dout1[52]
      DIRECTION OUTPUT ;
      PORT
         LAYER met4 ;
         RECT  639.505 226.055 639.885 226.435 ;
      END
   END dout1[52]
   PIN dout1[53]
      DIRECTION OUTPUT ;
      PORT
         LAYER met4 ;
         RECT  645.745 226.055 646.125 226.435 ;
      END
   END dout1[53]
   PIN dout1[54]
      DIRECTION OUTPUT ;
      PORT
         LAYER met4 ;
         RECT  651.985 226.055 652.365 226.435 ;
      END
   END dout1[54]
   PIN dout1[55]
      DIRECTION OUTPUT ;
      PORT
         LAYER met4 ;
         RECT  658.225 226.055 658.605 226.435 ;
      END
   END dout1[55]
   PIN dout1[56]
      DIRECTION OUTPUT ;
      PORT
         LAYER met4 ;
         RECT  664.465 226.055 664.845 226.435 ;
      END
   END dout1[56]
   PIN dout1[57]
      DIRECTION OUTPUT ;
      PORT
         LAYER met4 ;
         RECT  670.705 226.055 671.085 226.435 ;
      END
   END dout1[57]
   PIN dout1[58]
      DIRECTION OUTPUT ;
      PORT
         LAYER met4 ;
         RECT  676.945 226.055 677.325 226.435 ;
      END
   END dout1[58]
   PIN dout1[59]
      DIRECTION OUTPUT ;
      PORT
         LAYER met4 ;
         RECT  683.185 226.055 683.565 226.435 ;
      END
   END dout1[59]
   PIN dout1[60]
      DIRECTION OUTPUT ;
      PORT
         LAYER met4 ;
         RECT  689.425 226.055 689.805 226.435 ;
      END
   END dout1[60]
   PIN dout1[61]
      DIRECTION OUTPUT ;
      PORT
         LAYER met4 ;
         RECT  695.665 226.055 696.045 226.435 ;
      END
   END dout1[61]
   PIN dout1[62]
      DIRECTION OUTPUT ;
      PORT
         LAYER met4 ;
         RECT  701.905 226.055 702.285 226.435 ;
      END
   END dout1[62]
   PIN dout1[63]
      DIRECTION OUTPUT ;
      PORT
         LAYER met4 ;
         RECT  708.145 226.055 708.525 226.435 ;
      END
   END dout1[63]
   PIN dout1[64]
      DIRECTION OUTPUT ;
      PORT
         LAYER met4 ;
         RECT  714.385 226.055 714.765 226.435 ;
      END
   END dout1[64]
   PIN dout1[65]
      DIRECTION OUTPUT ;
      PORT
         LAYER met4 ;
         RECT  720.625 226.055 721.005 226.435 ;
      END
   END dout1[65]
   PIN dout1[66]
      DIRECTION OUTPUT ;
      PORT
         LAYER met4 ;
         RECT  726.865 226.055 727.245 226.435 ;
      END
   END dout1[66]
   PIN dout1[67]
      DIRECTION OUTPUT ;
      PORT
         LAYER met4 ;
         RECT  733.105 226.055 733.485 226.435 ;
      END
   END dout1[67]
   PIN dout1[68]
      DIRECTION OUTPUT ;
      PORT
         LAYER met4 ;
         RECT  739.345 226.055 739.725 226.435 ;
      END
   END dout1[68]
   PIN dout1[69]
      DIRECTION OUTPUT ;
      PORT
         LAYER met4 ;
         RECT  745.585 226.055 745.965 226.435 ;
      END
   END dout1[69]
   PIN dout1[70]
      DIRECTION OUTPUT ;
      PORT
         LAYER met4 ;
         RECT  751.825 226.055 752.205 226.435 ;
      END
   END dout1[70]
   PIN dout1[71]
      DIRECTION OUTPUT ;
      PORT
         LAYER met4 ;
         RECT  758.065 226.055 758.445 226.435 ;
      END
   END dout1[71]
   PIN dout1[72]
      DIRECTION OUTPUT ;
      PORT
         LAYER met4 ;
         RECT  764.305 226.055 764.685 226.435 ;
      END
   END dout1[72]
   PIN dout1[73]
      DIRECTION OUTPUT ;
      PORT
         LAYER met4 ;
         RECT  770.545 226.055 770.925 226.435 ;
      END
   END dout1[73]
   PIN dout1[74]
      DIRECTION OUTPUT ;
      PORT
         LAYER met4 ;
         RECT  776.785 226.055 777.165 226.435 ;
      END
   END dout1[74]
   PIN dout1[75]
      DIRECTION OUTPUT ;
      PORT
         LAYER met4 ;
         RECT  783.025 226.055 783.405 226.435 ;
      END
   END dout1[75]
   PIN dout1[76]
      DIRECTION OUTPUT ;
      PORT
         LAYER met4 ;
         RECT  789.265 226.055 789.645 226.435 ;
      END
   END dout1[76]
   PIN dout1[77]
      DIRECTION OUTPUT ;
      PORT
         LAYER met4 ;
         RECT  795.505 226.055 795.885 226.435 ;
      END
   END dout1[77]
   PIN dout1[78]
      DIRECTION OUTPUT ;
      PORT
         LAYER met4 ;
         RECT  801.745 226.055 802.125 226.435 ;
      END
   END dout1[78]
   PIN dout1[79]
      DIRECTION OUTPUT ;
      PORT
         LAYER met4 ;
         RECT  807.985 226.055 808.365 226.435 ;
      END
   END dout1[79]
   PIN dout1[80]
      DIRECTION OUTPUT ;
      PORT
         LAYER met4 ;
         RECT  814.225 226.055 814.605 226.435 ;
      END
   END dout1[80]
   PIN dout1[81]
      DIRECTION OUTPUT ;
      PORT
         LAYER met4 ;
         RECT  820.465 226.055 820.845 226.435 ;
      END
   END dout1[81]
   PIN dout1[82]
      DIRECTION OUTPUT ;
      PORT
         LAYER met4 ;
         RECT  826.705 226.055 827.085 226.435 ;
      END
   END dout1[82]
   PIN dout1[83]
      DIRECTION OUTPUT ;
      PORT
         LAYER met4 ;
         RECT  832.945 226.055 833.325 226.435 ;
      END
   END dout1[83]
   PIN dout1[84]
      DIRECTION OUTPUT ;
      PORT
         LAYER met4 ;
         RECT  839.185 226.055 839.565 226.435 ;
      END
   END dout1[84]
   PIN dout1[85]
      DIRECTION OUTPUT ;
      PORT
         LAYER met4 ;
         RECT  845.425 226.055 845.805 226.435 ;
      END
   END dout1[85]
   PIN dout1[86]
      DIRECTION OUTPUT ;
      PORT
         LAYER met4 ;
         RECT  851.665 226.055 852.045 226.435 ;
      END
   END dout1[86]
   PIN dout1[87]
      DIRECTION OUTPUT ;
      PORT
         LAYER met4 ;
         RECT  857.905 226.055 858.285 226.435 ;
      END
   END dout1[87]
   PIN dout1[88]
      DIRECTION OUTPUT ;
      PORT
         LAYER met4 ;
         RECT  864.145 226.055 864.525 226.435 ;
      END
   END dout1[88]
   PIN dout1[89]
      DIRECTION OUTPUT ;
      PORT
         LAYER met4 ;
         RECT  870.385 226.055 870.765 226.435 ;
      END
   END dout1[89]
   PIN dout1[90]
      DIRECTION OUTPUT ;
      PORT
         LAYER met4 ;
         RECT  876.625 226.055 877.005 226.435 ;
      END
   END dout1[90]
   PIN dout1[91]
      DIRECTION OUTPUT ;
      PORT
         LAYER met4 ;
         RECT  882.865 226.055 883.245 226.435 ;
      END
   END dout1[91]
   PIN dout1[92]
      DIRECTION OUTPUT ;
      PORT
         LAYER met4 ;
         RECT  889.105 226.055 889.485 226.435 ;
      END
   END dout1[92]
   PIN dout1[93]
      DIRECTION OUTPUT ;
      PORT
         LAYER met4 ;
         RECT  895.345 226.055 895.725 226.435 ;
      END
   END dout1[93]
   PIN dout1[94]
      DIRECTION OUTPUT ;
      PORT
         LAYER met4 ;
         RECT  901.585 226.055 901.965 226.435 ;
      END
   END dout1[94]
   PIN dout1[95]
      DIRECTION OUTPUT ;
      PORT
         LAYER met4 ;
         RECT  907.825 226.055 908.205 226.435 ;
      END
   END dout1[95]
   PIN dout1[96]
      DIRECTION OUTPUT ;
      PORT
         LAYER met4 ;
         RECT  914.065 226.055 914.445 226.435 ;
      END
   END dout1[96]
   PIN dout1[97]
      DIRECTION OUTPUT ;
      PORT
         LAYER met4 ;
         RECT  920.305 226.055 920.685 226.435 ;
      END
   END dout1[97]
   PIN dout1[98]
      DIRECTION OUTPUT ;
      PORT
         LAYER met4 ;
         RECT  926.545 226.055 926.925 226.435 ;
      END
   END dout1[98]
   PIN dout1[99]
      DIRECTION OUTPUT ;
      PORT
         LAYER met4 ;
         RECT  932.785 226.055 933.165 226.435 ;
      END
   END dout1[99]
   PIN dout1[100]
      DIRECTION OUTPUT ;
      PORT
         LAYER met4 ;
         RECT  939.025 226.055 939.405 226.435 ;
      END
   END dout1[100]
   PIN dout1[101]
      DIRECTION OUTPUT ;
      PORT
         LAYER met4 ;
         RECT  945.265 226.055 945.645 226.435 ;
      END
   END dout1[101]
   PIN dout1[102]
      DIRECTION OUTPUT ;
      PORT
         LAYER met4 ;
         RECT  951.505 226.055 951.885 226.435 ;
      END
   END dout1[102]
   PIN dout1[103]
      DIRECTION OUTPUT ;
      PORT
         LAYER met4 ;
         RECT  957.745 226.055 958.125 226.435 ;
      END
   END dout1[103]
   PIN dout1[104]
      DIRECTION OUTPUT ;
      PORT
         LAYER met4 ;
         RECT  963.985 226.055 964.365 226.435 ;
      END
   END dout1[104]
   PIN dout1[105]
      DIRECTION OUTPUT ;
      PORT
         LAYER met4 ;
         RECT  970.225 226.055 970.605 226.435 ;
      END
   END dout1[105]
   PIN dout1[106]
      DIRECTION OUTPUT ;
      PORT
         LAYER met4 ;
         RECT  976.465 226.055 976.845 226.435 ;
      END
   END dout1[106]
   PIN dout1[107]
      DIRECTION OUTPUT ;
      PORT
         LAYER met4 ;
         RECT  982.705 226.055 983.085 226.435 ;
      END
   END dout1[107]
   PIN dout1[108]
      DIRECTION OUTPUT ;
      PORT
         LAYER met4 ;
         RECT  988.945 226.055 989.325 226.435 ;
      END
   END dout1[108]
   PIN dout1[109]
      DIRECTION OUTPUT ;
      PORT
         LAYER met4 ;
         RECT  995.185 226.055 995.565 226.435 ;
      END
   END dout1[109]
   PIN dout1[110]
      DIRECTION OUTPUT ;
      PORT
         LAYER met4 ;
         RECT  1001.425 226.055 1001.805 226.435 ;
      END
   END dout1[110]
   PIN dout1[111]
      DIRECTION OUTPUT ;
      PORT
         LAYER met4 ;
         RECT  1007.665 226.055 1008.045 226.435 ;
      END
   END dout1[111]
   PIN dout1[112]
      DIRECTION OUTPUT ;
      PORT
         LAYER met4 ;
         RECT  1013.905 226.055 1014.285 226.435 ;
      END
   END dout1[112]
   PIN dout1[113]
      DIRECTION OUTPUT ;
      PORT
         LAYER met4 ;
         RECT  1020.145 226.055 1020.525 226.435 ;
      END
   END dout1[113]
   PIN dout1[114]
      DIRECTION OUTPUT ;
      PORT
         LAYER met4 ;
         RECT  1026.385 226.055 1026.765 226.435 ;
      END
   END dout1[114]
   PIN dout1[115]
      DIRECTION OUTPUT ;
      PORT
         LAYER met4 ;
         RECT  1032.625 226.055 1033.005 226.435 ;
      END
   END dout1[115]
   PIN dout1[116]
      DIRECTION OUTPUT ;
      PORT
         LAYER met4 ;
         RECT  1038.865 226.055 1039.245 226.435 ;
      END
   END dout1[116]
   PIN dout1[117]
      DIRECTION OUTPUT ;
      PORT
         LAYER met4 ;
         RECT  1045.105 226.055 1045.485 226.435 ;
      END
   END dout1[117]
   PIN dout1[118]
      DIRECTION OUTPUT ;
      PORT
         LAYER met4 ;
         RECT  1051.345 226.055 1051.725 226.435 ;
      END
   END dout1[118]
   PIN dout1[119]
      DIRECTION OUTPUT ;
      PORT
         LAYER met4 ;
         RECT  1057.585 226.055 1057.965 226.435 ;
      END
   END dout1[119]
   PIN dout1[120]
      DIRECTION OUTPUT ;
      PORT
         LAYER met4 ;
         RECT  1063.825 226.055 1064.205 226.435 ;
      END
   END dout1[120]
   PIN dout1[121]
      DIRECTION OUTPUT ;
      PORT
         LAYER met4 ;
         RECT  1070.065 226.055 1070.445 226.435 ;
      END
   END dout1[121]
   PIN dout1[122]
      DIRECTION OUTPUT ;
      PORT
         LAYER met4 ;
         RECT  1076.305 226.055 1076.685 226.435 ;
      END
   END dout1[122]
   PIN dout1[123]
      DIRECTION OUTPUT ;
      PORT
         LAYER met4 ;
         RECT  1082.545 226.055 1082.925 226.435 ;
      END
   END dout1[123]
   PIN dout1[124]
      DIRECTION OUTPUT ;
      PORT
         LAYER met4 ;
         RECT  1088.785 226.055 1089.165 226.435 ;
      END
   END dout1[124]
   PIN dout1[125]
      DIRECTION OUTPUT ;
      PORT
         LAYER met4 ;
         RECT  1095.025 226.055 1095.405 226.435 ;
      END
   END dout1[125]
   PIN dout1[126]
      DIRECTION OUTPUT ;
      PORT
         LAYER met4 ;
         RECT  1101.265 226.055 1101.645 226.435 ;
      END
   END dout1[126]
   PIN dout1[127]
      DIRECTION OUTPUT ;
      PORT
         LAYER met4 ;
         RECT  1107.505 226.055 1107.885 226.435 ;
      END
   END dout1[127]
   PIN dout1[128]
      DIRECTION OUTPUT ;
      PORT
         LAYER met4 ;
         RECT  1113.745 226.055 1114.125 226.435 ;
      END
   END dout1[128]
   PIN dout1[129]
      DIRECTION OUTPUT ;
      PORT
         LAYER met4 ;
         RECT  1119.985 226.055 1120.365 226.435 ;
      END
   END dout1[129]
   PIN dout1[130]
      DIRECTION OUTPUT ;
      PORT
         LAYER met4 ;
         RECT  1126.225 226.055 1126.605 226.435 ;
      END
   END dout1[130]
   PIN dout1[131]
      DIRECTION OUTPUT ;
      PORT
         LAYER met4 ;
         RECT  1132.465 226.055 1132.845 226.435 ;
      END
   END dout1[131]
   PIN dout1[132]
      DIRECTION OUTPUT ;
      PORT
         LAYER met4 ;
         RECT  1138.705 226.055 1139.085 226.435 ;
      END
   END dout1[132]
   PIN dout1[133]
      DIRECTION OUTPUT ;
      PORT
         LAYER met4 ;
         RECT  1144.945 226.055 1145.325 226.435 ;
      END
   END dout1[133]
   PIN dout1[134]
      DIRECTION OUTPUT ;
      PORT
         LAYER met4 ;
         RECT  1151.185 226.055 1151.565 226.435 ;
      END
   END dout1[134]
   PIN dout1[135]
      DIRECTION OUTPUT ;
      PORT
         LAYER met4 ;
         RECT  1157.425 226.055 1157.805 226.435 ;
      END
   END dout1[135]
   PIN dout1[136]
      DIRECTION OUTPUT ;
      PORT
         LAYER met4 ;
         RECT  1163.665 226.055 1164.045 226.435 ;
      END
   END dout1[136]
   PIN dout1[137]
      DIRECTION OUTPUT ;
      PORT
         LAYER met4 ;
         RECT  1169.905 226.055 1170.285 226.435 ;
      END
   END dout1[137]
   PIN dout1[138]
      DIRECTION OUTPUT ;
      PORT
         LAYER met4 ;
         RECT  1176.145 226.055 1176.525 226.435 ;
      END
   END dout1[138]
   PIN dout1[139]
      DIRECTION OUTPUT ;
      PORT
         LAYER met4 ;
         RECT  1182.385 226.055 1182.765 226.435 ;
      END
   END dout1[139]
   PIN dout1[140]
      DIRECTION OUTPUT ;
      PORT
         LAYER met4 ;
         RECT  1188.625 226.055 1189.005 226.435 ;
      END
   END dout1[140]
   PIN dout1[141]
      DIRECTION OUTPUT ;
      PORT
         LAYER met4 ;
         RECT  1194.865 226.055 1195.245 226.435 ;
      END
   END dout1[141]
   PIN dout1[142]
      DIRECTION OUTPUT ;
      PORT
         LAYER met4 ;
         RECT  1201.105 226.055 1201.485 226.435 ;
      END
   END dout1[142]
   PIN dout1[143]
      DIRECTION OUTPUT ;
      PORT
         LAYER met4 ;
         RECT  1207.345 226.055 1207.725 226.435 ;
      END
   END dout1[143]
   PIN dout1[144]
      DIRECTION OUTPUT ;
      PORT
         LAYER met4 ;
         RECT  1213.585 226.055 1213.965 226.435 ;
      END
   END dout1[144]
   PIN dout1[145]
      DIRECTION OUTPUT ;
      PORT
         LAYER met4 ;
         RECT  1219.825 226.055 1220.205 226.435 ;
      END
   END dout1[145]
   PIN dout1[146]
      DIRECTION OUTPUT ;
      PORT
         LAYER met4 ;
         RECT  1226.065 226.055 1226.445 226.435 ;
      END
   END dout1[146]
   PIN dout1[147]
      DIRECTION OUTPUT ;
      PORT
         LAYER met4 ;
         RECT  1232.305 226.055 1232.685 226.435 ;
      END
   END dout1[147]
   PIN dout1[148]
      DIRECTION OUTPUT ;
      PORT
         LAYER met4 ;
         RECT  1238.545 226.055 1238.925 226.435 ;
      END
   END dout1[148]
   PIN dout1[149]
      DIRECTION OUTPUT ;
      PORT
         LAYER met4 ;
         RECT  1244.785 226.055 1245.165 226.435 ;
      END
   END dout1[149]
   PIN dout1[150]
      DIRECTION OUTPUT ;
      PORT
         LAYER met4 ;
         RECT  1251.025 226.055 1251.405 226.435 ;
      END
   END dout1[150]
   PIN dout1[151]
      DIRECTION OUTPUT ;
      PORT
         LAYER met4 ;
         RECT  1257.265 226.055 1257.645 226.435 ;
      END
   END dout1[151]
   PIN dout1[152]
      DIRECTION OUTPUT ;
      PORT
         LAYER met4 ;
         RECT  1263.505 226.055 1263.885 226.435 ;
      END
   END dout1[152]
   PIN dout1[153]
      DIRECTION OUTPUT ;
      PORT
         LAYER met4 ;
         RECT  1269.745 226.055 1270.125 226.435 ;
      END
   END dout1[153]
   PIN dout1[154]
      DIRECTION OUTPUT ;
      PORT
         LAYER met4 ;
         RECT  1275.985 226.055 1276.365 226.435 ;
      END
   END dout1[154]
   PIN dout1[155]
      DIRECTION OUTPUT ;
      PORT
         LAYER met4 ;
         RECT  1282.225 226.055 1282.605 226.435 ;
      END
   END dout1[155]
   PIN dout1[156]
      DIRECTION OUTPUT ;
      PORT
         LAYER met4 ;
         RECT  1288.465 226.055 1288.845 226.435 ;
      END
   END dout1[156]
   PIN dout1[157]
      DIRECTION OUTPUT ;
      PORT
         LAYER met4 ;
         RECT  1294.705 226.055 1295.085 226.435 ;
      END
   END dout1[157]
   PIN dout1[158]
      DIRECTION OUTPUT ;
      PORT
         LAYER met4 ;
         RECT  1300.945 226.055 1301.325 226.435 ;
      END
   END dout1[158]
   PIN dout1[159]
      DIRECTION OUTPUT ;
      PORT
         LAYER met4 ;
         RECT  1307.185 226.055 1307.565 226.435 ;
      END
   END dout1[159]
   PIN dout1[160]
      DIRECTION OUTPUT ;
      PORT
         LAYER met4 ;
         RECT  1313.425 226.055 1313.805 226.435 ;
      END
   END dout1[160]
   PIN dout1[161]
      DIRECTION OUTPUT ;
      PORT
         LAYER met4 ;
         RECT  1319.665 226.055 1320.045 226.435 ;
      END
   END dout1[161]
   PIN dout1[162]
      DIRECTION OUTPUT ;
      PORT
         LAYER met4 ;
         RECT  1325.905 226.055 1326.285 226.435 ;
      END
   END dout1[162]
   PIN dout1[163]
      DIRECTION OUTPUT ;
      PORT
         LAYER met4 ;
         RECT  1332.145 226.055 1332.525 226.435 ;
      END
   END dout1[163]
   PIN dout1[164]
      DIRECTION OUTPUT ;
      PORT
         LAYER met4 ;
         RECT  1338.385 226.055 1338.765 226.435 ;
      END
   END dout1[164]
   PIN dout1[165]
      DIRECTION OUTPUT ;
      PORT
         LAYER met4 ;
         RECT  1344.625 226.055 1345.005 226.435 ;
      END
   END dout1[165]
   PIN dout1[166]
      DIRECTION OUTPUT ;
      PORT
         LAYER met4 ;
         RECT  1350.865 226.055 1351.245 226.435 ;
      END
   END dout1[166]
   PIN dout1[167]
      DIRECTION OUTPUT ;
      PORT
         LAYER met4 ;
         RECT  1357.105 226.055 1357.485 226.435 ;
      END
   END dout1[167]
   PIN dout1[168]
      DIRECTION OUTPUT ;
      PORT
         LAYER met4 ;
         RECT  1363.345 226.055 1363.725 226.435 ;
      END
   END dout1[168]
   PIN dout1[169]
      DIRECTION OUTPUT ;
      PORT
         LAYER met4 ;
         RECT  1369.585 226.055 1369.965 226.435 ;
      END
   END dout1[169]
   PIN dout1[170]
      DIRECTION OUTPUT ;
      PORT
         LAYER met4 ;
         RECT  1375.825 226.055 1376.205 226.435 ;
      END
   END dout1[170]
   PIN dout1[171]
      DIRECTION OUTPUT ;
      PORT
         LAYER met4 ;
         RECT  1382.065 226.055 1382.445 226.435 ;
      END
   END dout1[171]
   PIN dout1[172]
      DIRECTION OUTPUT ;
      PORT
         LAYER met4 ;
         RECT  1388.305 226.055 1388.685 226.435 ;
      END
   END dout1[172]
   PIN dout1[173]
      DIRECTION OUTPUT ;
      PORT
         LAYER met4 ;
         RECT  1394.545 226.055 1394.925 226.435 ;
      END
   END dout1[173]
   PIN dout1[174]
      DIRECTION OUTPUT ;
      PORT
         LAYER met4 ;
         RECT  1400.785 226.055 1401.165 226.435 ;
      END
   END dout1[174]
   PIN dout1[175]
      DIRECTION OUTPUT ;
      PORT
         LAYER met4 ;
         RECT  1407.025 226.055 1407.405 226.435 ;
      END
   END dout1[175]
   PIN dout1[176]
      DIRECTION OUTPUT ;
      PORT
         LAYER met4 ;
         RECT  1413.265 226.055 1413.645 226.435 ;
      END
   END dout1[176]
   PIN dout1[177]
      DIRECTION OUTPUT ;
      PORT
         LAYER met4 ;
         RECT  1419.505 226.055 1419.885 226.435 ;
      END
   END dout1[177]
   PIN dout1[178]
      DIRECTION OUTPUT ;
      PORT
         LAYER met4 ;
         RECT  1425.745 226.055 1426.125 226.435 ;
      END
   END dout1[178]
   PIN dout1[179]
      DIRECTION OUTPUT ;
      PORT
         LAYER met4 ;
         RECT  1431.985 226.055 1432.365 226.435 ;
      END
   END dout1[179]
   PIN dout1[180]
      DIRECTION OUTPUT ;
      PORT
         LAYER met4 ;
         RECT  1438.225 226.055 1438.605 226.435 ;
      END
   END dout1[180]
   PIN dout1[181]
      DIRECTION OUTPUT ;
      PORT
         LAYER met4 ;
         RECT  1444.465 226.055 1444.845 226.435 ;
      END
   END dout1[181]
   PIN dout1[182]
      DIRECTION OUTPUT ;
      PORT
         LAYER met4 ;
         RECT  1450.705 226.055 1451.085 226.435 ;
      END
   END dout1[182]
   PIN dout1[183]
      DIRECTION OUTPUT ;
      PORT
         LAYER met4 ;
         RECT  1456.945 226.055 1457.325 226.435 ;
      END
   END dout1[183]
   PIN dout1[184]
      DIRECTION OUTPUT ;
      PORT
         LAYER met4 ;
         RECT  1463.185 226.055 1463.565 226.435 ;
      END
   END dout1[184]
   PIN dout1[185]
      DIRECTION OUTPUT ;
      PORT
         LAYER met4 ;
         RECT  1469.425 226.055 1469.805 226.435 ;
      END
   END dout1[185]
   PIN dout1[186]
      DIRECTION OUTPUT ;
      PORT
         LAYER met4 ;
         RECT  1475.665 226.055 1476.045 226.435 ;
      END
   END dout1[186]
   PIN dout1[187]
      DIRECTION OUTPUT ;
      PORT
         LAYER met4 ;
         RECT  1481.905 226.055 1482.285 226.435 ;
      END
   END dout1[187]
   PIN dout1[188]
      DIRECTION OUTPUT ;
      PORT
         LAYER met4 ;
         RECT  1488.145 226.055 1488.525 226.435 ;
      END
   END dout1[188]
   PIN dout1[189]
      DIRECTION OUTPUT ;
      PORT
         LAYER met4 ;
         RECT  1494.385 226.055 1494.765 226.435 ;
      END
   END dout1[189]
   PIN dout1[190]
      DIRECTION OUTPUT ;
      PORT
         LAYER met4 ;
         RECT  1500.625 226.055 1501.005 226.435 ;
      END
   END dout1[190]
   PIN dout1[191]
      DIRECTION OUTPUT ;
      PORT
         LAYER met4 ;
         RECT  1506.865 226.055 1507.245 226.435 ;
      END
   END dout1[191]
   PIN dout1[192]
      DIRECTION OUTPUT ;
      PORT
         LAYER met4 ;
         RECT  1513.105 226.055 1513.485 226.435 ;
      END
   END dout1[192]
   PIN dout1[193]
      DIRECTION OUTPUT ;
      PORT
         LAYER met4 ;
         RECT  1519.345 226.055 1519.725 226.435 ;
      END
   END dout1[193]
   PIN dout1[194]
      DIRECTION OUTPUT ;
      PORT
         LAYER met4 ;
         RECT  1525.585 226.055 1525.965 226.435 ;
      END
   END dout1[194]
   PIN dout1[195]
      DIRECTION OUTPUT ;
      PORT
         LAYER met4 ;
         RECT  1531.825 226.055 1532.205 226.435 ;
      END
   END dout1[195]
   PIN dout1[196]
      DIRECTION OUTPUT ;
      PORT
         LAYER met4 ;
         RECT  1538.065 226.055 1538.445 226.435 ;
      END
   END dout1[196]
   PIN dout1[197]
      DIRECTION OUTPUT ;
      PORT
         LAYER met4 ;
         RECT  1544.305 226.055 1544.685 226.435 ;
      END
   END dout1[197]
   PIN dout1[198]
      DIRECTION OUTPUT ;
      PORT
         LAYER met4 ;
         RECT  1550.545 226.055 1550.925 226.435 ;
      END
   END dout1[198]
   PIN dout1[199]
      DIRECTION OUTPUT ;
      PORT
         LAYER met4 ;
         RECT  1556.785 226.055 1557.165 226.435 ;
      END
   END dout1[199]
   PIN dout1[200]
      DIRECTION OUTPUT ;
      PORT
         LAYER met4 ;
         RECT  1563.025 226.055 1563.405 226.435 ;
      END
   END dout1[200]
   PIN dout1[201]
      DIRECTION OUTPUT ;
      PORT
         LAYER met4 ;
         RECT  1569.265 226.055 1569.645 226.435 ;
      END
   END dout1[201]
   PIN dout1[202]
      DIRECTION OUTPUT ;
      PORT
         LAYER met4 ;
         RECT  1575.505 226.055 1575.885 226.435 ;
      END
   END dout1[202]
   PIN dout1[203]
      DIRECTION OUTPUT ;
      PORT
         LAYER met4 ;
         RECT  1581.745 226.055 1582.125 226.435 ;
      END
   END dout1[203]
   PIN dout1[204]
      DIRECTION OUTPUT ;
      PORT
         LAYER met4 ;
         RECT  1587.985 226.055 1588.365 226.435 ;
      END
   END dout1[204]
   PIN dout1[205]
      DIRECTION OUTPUT ;
      PORT
         LAYER met4 ;
         RECT  1594.225 226.055 1594.605 226.435 ;
      END
   END dout1[205]
   PIN dout1[206]
      DIRECTION OUTPUT ;
      PORT
         LAYER met4 ;
         RECT  1600.465 226.055 1600.845 226.435 ;
      END
   END dout1[206]
   PIN dout1[207]
      DIRECTION OUTPUT ;
      PORT
         LAYER met4 ;
         RECT  1606.705 226.055 1607.085 226.435 ;
      END
   END dout1[207]
   PIN dout1[208]
      DIRECTION OUTPUT ;
      PORT
         LAYER met4 ;
         RECT  1612.945 226.055 1613.325 226.435 ;
      END
   END dout1[208]
   PIN dout1[209]
      DIRECTION OUTPUT ;
      PORT
         LAYER met4 ;
         RECT  1619.185 226.055 1619.565 226.435 ;
      END
   END dout1[209]
   PIN dout1[210]
      DIRECTION OUTPUT ;
      PORT
         LAYER met4 ;
         RECT  1625.425 226.055 1625.805 226.435 ;
      END
   END dout1[210]
   PIN dout1[211]
      DIRECTION OUTPUT ;
      PORT
         LAYER met4 ;
         RECT  1631.665 226.055 1632.045 226.435 ;
      END
   END dout1[211]
   PIN dout1[212]
      DIRECTION OUTPUT ;
      PORT
         LAYER met4 ;
         RECT  1637.905 226.055 1638.285 226.435 ;
      END
   END dout1[212]
   PIN dout1[213]
      DIRECTION OUTPUT ;
      PORT
         LAYER met4 ;
         RECT  1644.145 226.055 1644.525 226.435 ;
      END
   END dout1[213]
   PIN dout1[214]
      DIRECTION OUTPUT ;
      PORT
         LAYER met4 ;
         RECT  1650.385 226.055 1650.765 226.435 ;
      END
   END dout1[214]
   PIN dout1[215]
      DIRECTION OUTPUT ;
      PORT
         LAYER met4 ;
         RECT  1656.625 226.055 1657.005 226.435 ;
      END
   END dout1[215]
   PIN dout1[216]
      DIRECTION OUTPUT ;
      PORT
         LAYER met4 ;
         RECT  1662.865 226.055 1663.245 226.435 ;
      END
   END dout1[216]
   PIN dout1[217]
      DIRECTION OUTPUT ;
      PORT
         LAYER met4 ;
         RECT  1669.105 226.055 1669.485 226.435 ;
      END
   END dout1[217]
   PIN dout1[218]
      DIRECTION OUTPUT ;
      PORT
         LAYER met4 ;
         RECT  1675.345 226.055 1675.725 226.435 ;
      END
   END dout1[218]
   PIN dout1[219]
      DIRECTION OUTPUT ;
      PORT
         LAYER met4 ;
         RECT  1681.585 226.055 1681.965 226.435 ;
      END
   END dout1[219]
   PIN dout1[220]
      DIRECTION OUTPUT ;
      PORT
         LAYER met4 ;
         RECT  1687.825 226.055 1688.205 226.435 ;
      END
   END dout1[220]
   PIN dout1[221]
      DIRECTION OUTPUT ;
      PORT
         LAYER met4 ;
         RECT  1694.065 226.055 1694.445 226.435 ;
      END
   END dout1[221]
   PIN dout1[222]
      DIRECTION OUTPUT ;
      PORT
         LAYER met4 ;
         RECT  1700.305 226.055 1700.685 226.435 ;
      END
   END dout1[222]
   PIN dout1[223]
      DIRECTION OUTPUT ;
      PORT
         LAYER met4 ;
         RECT  1706.545 226.055 1706.925 226.435 ;
      END
   END dout1[223]
   PIN dout1[224]
      DIRECTION OUTPUT ;
      PORT
         LAYER met4 ;
         RECT  1712.785 226.055 1713.165 226.435 ;
      END
   END dout1[224]
   PIN dout1[225]
      DIRECTION OUTPUT ;
      PORT
         LAYER met4 ;
         RECT  1719.025 226.055 1719.405 226.435 ;
      END
   END dout1[225]
   PIN dout1[226]
      DIRECTION OUTPUT ;
      PORT
         LAYER met4 ;
         RECT  1725.265 226.055 1725.645 226.435 ;
      END
   END dout1[226]
   PIN dout1[227]
      DIRECTION OUTPUT ;
      PORT
         LAYER met4 ;
         RECT  1731.505 226.055 1731.885 226.435 ;
      END
   END dout1[227]
   PIN dout1[228]
      DIRECTION OUTPUT ;
      PORT
         LAYER met4 ;
         RECT  1737.745 226.055 1738.125 226.435 ;
      END
   END dout1[228]
   PIN dout1[229]
      DIRECTION OUTPUT ;
      PORT
         LAYER met4 ;
         RECT  1743.985 226.055 1744.365 226.435 ;
      END
   END dout1[229]
   PIN dout1[230]
      DIRECTION OUTPUT ;
      PORT
         LAYER met4 ;
         RECT  1750.225 226.055 1750.605 226.435 ;
      END
   END dout1[230]
   PIN dout1[231]
      DIRECTION OUTPUT ;
      PORT
         LAYER met4 ;
         RECT  1756.465 226.055 1756.845 226.435 ;
      END
   END dout1[231]
   PIN dout1[232]
      DIRECTION OUTPUT ;
      PORT
         LAYER met4 ;
         RECT  1762.705 226.055 1763.085 226.435 ;
      END
   END dout1[232]
   PIN dout1[233]
      DIRECTION OUTPUT ;
      PORT
         LAYER met4 ;
         RECT  1768.945 226.055 1769.325 226.435 ;
      END
   END dout1[233]
   PIN dout1[234]
      DIRECTION OUTPUT ;
      PORT
         LAYER met4 ;
         RECT  1775.185 226.055 1775.565 226.435 ;
      END
   END dout1[234]
   PIN dout1[235]
      DIRECTION OUTPUT ;
      PORT
         LAYER met4 ;
         RECT  1781.425 226.055 1781.805 226.435 ;
      END
   END dout1[235]
   PIN dout1[236]
      DIRECTION OUTPUT ;
      PORT
         LAYER met4 ;
         RECT  1787.665 226.055 1788.045 226.435 ;
      END
   END dout1[236]
   PIN dout1[237]
      DIRECTION OUTPUT ;
      PORT
         LAYER met4 ;
         RECT  1793.905 226.055 1794.285 226.435 ;
      END
   END dout1[237]
   PIN dout1[238]
      DIRECTION OUTPUT ;
      PORT
         LAYER met4 ;
         RECT  1800.145 226.055 1800.525 226.435 ;
      END
   END dout1[238]
   PIN dout1[239]
      DIRECTION OUTPUT ;
      PORT
         LAYER met4 ;
         RECT  1806.385 226.055 1806.765 226.435 ;
      END
   END dout1[239]
   PIN dout1[240]
      DIRECTION OUTPUT ;
      PORT
         LAYER met4 ;
         RECT  1812.625 226.055 1813.005 226.435 ;
      END
   END dout1[240]
   PIN dout1[241]
      DIRECTION OUTPUT ;
      PORT
         LAYER met4 ;
         RECT  1818.865 226.055 1819.245 226.435 ;
      END
   END dout1[241]
   PIN dout1[242]
      DIRECTION OUTPUT ;
      PORT
         LAYER met4 ;
         RECT  1825.105 226.055 1825.485 226.435 ;
      END
   END dout1[242]
   PIN dout1[243]
      DIRECTION OUTPUT ;
      PORT
         LAYER met4 ;
         RECT  1831.345 226.055 1831.725 226.435 ;
      END
   END dout1[243]
   PIN dout1[244]
      DIRECTION OUTPUT ;
      PORT
         LAYER met4 ;
         RECT  1837.585 226.055 1837.965 226.435 ;
      END
   END dout1[244]
   PIN dout1[245]
      DIRECTION OUTPUT ;
      PORT
         LAYER met4 ;
         RECT  1843.825 226.055 1844.205 226.435 ;
      END
   END dout1[245]
   PIN dout1[246]
      DIRECTION OUTPUT ;
      PORT
         LAYER met4 ;
         RECT  1850.065 226.055 1850.445 226.435 ;
      END
   END dout1[246]
   PIN dout1[247]
      DIRECTION OUTPUT ;
      PORT
         LAYER met4 ;
         RECT  1856.305 226.055 1856.685 226.435 ;
      END
   END dout1[247]
   PIN dout1[248]
      DIRECTION OUTPUT ;
      PORT
         LAYER met4 ;
         RECT  1862.545 226.055 1862.925 226.435 ;
      END
   END dout1[248]
   PIN dout1[249]
      DIRECTION OUTPUT ;
      PORT
         LAYER met4 ;
         RECT  1868.785 226.055 1869.165 226.435 ;
      END
   END dout1[249]
   PIN dout1[250]
      DIRECTION OUTPUT ;
      PORT
         LAYER met4 ;
         RECT  1875.025 226.055 1875.405 226.435 ;
      END
   END dout1[250]
   PIN dout1[251]
      DIRECTION OUTPUT ;
      PORT
         LAYER met4 ;
         RECT  1881.265 226.055 1881.645 226.435 ;
      END
   END dout1[251]
   PIN dout1[252]
      DIRECTION OUTPUT ;
      PORT
         LAYER met4 ;
         RECT  1887.505 226.055 1887.885 226.435 ;
      END
   END dout1[252]
   PIN dout1[253]
      DIRECTION OUTPUT ;
      PORT
         LAYER met4 ;
         RECT  1893.745 226.055 1894.125 226.435 ;
      END
   END dout1[253]
   PIN dout1[254]
      DIRECTION OUTPUT ;
      PORT
         LAYER met4 ;
         RECT  1899.985 226.055 1900.365 226.435 ;
      END
   END dout1[254]
   PIN dout1[255]
      DIRECTION OUTPUT ;
      PORT
         LAYER met4 ;
         RECT  1906.225 226.055 1906.605 226.435 ;
      END
   END dout1[255]
   PIN dout1[256]
      DIRECTION OUTPUT ;
      PORT
         LAYER met4 ;
         RECT  1912.465 226.055 1912.845 226.435 ;
      END
   END dout1[256]
   PIN vccd1
      DIRECTION INOUT ;
      USE POWER ; 
      SHAPE ABUTMENT ; 
      PORT
         LAYER met3 ;
         RECT  0.0 224.695 2228.76 226.435 ;
         LAYER met3 ;
         RECT  0.0 0.0 2228.76 1.74 ;
         LAYER met4 ;
         RECT  0.0 0.0 1.74 226.435 ;
         LAYER met4 ;
         RECT  2227.02 0.0 2228.76 226.435 ;
      END
   END vccd1
   PIN vssd1
      DIRECTION INOUT ;
      USE GROUND ; 
      SHAPE ABUTMENT ; 
      PORT
         LAYER met4 ;
         RECT  2223.54 3.48 2225.28 222.955 ;
         LAYER met3 ;
         RECT  3.48 221.215 2225.28 222.955 ;
         LAYER met3 ;
         RECT  3.48 3.48 2225.28 5.22 ;
         LAYER met4 ;
         RECT  3.48 3.48 5.22 222.955 ;
      END
   END vssd1
   OBS
   LAYER  met1 ;
      RECT  0.62 0.62 2228.14 225.815 ;
   LAYER  met2 ;
      RECT  0.62 0.62 2228.14 225.815 ;
   LAYER  met3 ;
      RECT  0.98 40.705 2228.14 42.285 ;
      RECT  0.98 42.285 2227.78 211.275 ;
      RECT  0.98 211.275 2227.78 212.855 ;
      RECT  2227.78 42.285 2228.14 211.275 ;
      RECT  0.62 43.03 0.98 49.205 ;
      RECT  2227.78 212.855 2228.14 224.095 ;
      RECT  0.62 50.785 0.98 224.095 ;
      RECT  0.62 2.34 0.98 40.705 ;
      RECT  0.98 212.855 2.88 220.615 ;
      RECT  0.98 220.615 2.88 223.555 ;
      RECT  0.98 223.555 2.88 224.095 ;
      RECT  2.88 212.855 2225.88 220.615 ;
      RECT  2.88 223.555 2225.88 224.095 ;
      RECT  2225.88 212.855 2227.78 220.615 ;
      RECT  2225.88 220.615 2227.78 223.555 ;
      RECT  2225.88 223.555 2227.78 224.095 ;
      RECT  0.98 2.34 2.88 2.88 ;
      RECT  0.98 2.88 2.88 5.82 ;
      RECT  0.98 5.82 2.88 40.705 ;
      RECT  2.88 2.34 2225.88 2.88 ;
      RECT  2.88 5.82 2225.88 40.705 ;
      RECT  2225.88 2.34 2228.14 2.88 ;
      RECT  2225.88 2.88 2228.14 5.82 ;
      RECT  2225.88 5.82 2228.14 40.705 ;
   LAYER  met4 ;
      RECT  257.08 0.98 258.66 225.815 ;
      RECT  258.66 0.62 262.92 0.98 ;
      RECT  264.5 0.62 268.76 0.98 ;
      RECT  270.34 0.62 274.6 0.98 ;
      RECT  276.18 0.62 280.44 0.98 ;
      RECT  282.02 0.62 286.28 0.98 ;
      RECT  287.86 0.62 292.12 0.98 ;
      RECT  293.7 0.62 297.96 0.98 ;
      RECT  299.54 0.62 303.8 0.98 ;
      RECT  305.38 0.62 309.64 0.98 ;
      RECT  322.9 0.62 327.16 0.98 ;
      RECT  416.34 0.62 420.6 0.98 ;
      RECT  503.94 0.62 508.2 0.98 ;
      RECT  597.38 0.62 601.64 0.98 ;
      RECT  684.98 0.62 689.24 0.98 ;
      RECT  778.42 0.62 782.68 0.98 ;
      RECT  871.86 0.62 876.12 0.98 ;
      RECT  959.46 0.62 963.72 0.98 ;
      RECT  1052.9 0.62 1057.16 0.98 ;
      RECT  1140.5 0.62 1144.76 0.98 ;
      RECT  1233.94 0.62 1238.2 0.98 ;
      RECT  1327.38 0.62 1331.64 0.98 ;
      RECT  1414.98 0.62 1419.24 0.98 ;
      RECT  1508.42 0.62 1512.68 0.98 ;
      RECT  1596.02 0.62 1600.28 0.98 ;
      RECT  1689.46 0.62 1693.72 0.98 ;
      RECT  252.82 0.62 257.08 0.98 ;
      RECT  237.33 0.98 238.91 225.455 ;
      RECT  238.91 0.98 257.08 225.455 ;
      RECT  243.265 225.455 257.08 225.815 ;
      RECT  258.66 0.98 1971.48 225.455 ;
      RECT  1971.48 0.98 1973.06 225.455 ;
      RECT  1973.06 225.455 2197.52 225.815 ;
      RECT  311.22 0.62 313.675 0.98 ;
      RECT  315.255 0.62 315.48 0.98 ;
      RECT  317.06 0.62 319.515 0.98 ;
      RECT  321.095 0.62 321.32 0.98 ;
      RECT  329.805 0.62 333.0 0.98 ;
      RECT  335.27 0.62 338.84 0.98 ;
      RECT  341.11 0.62 344.68 0.98 ;
      RECT  347.145 0.62 350.52 0.98 ;
      RECT  353.385 0.62 356.36 0.98 ;
      RECT  357.94 0.62 358.045 0.98 ;
      RECT  359.625 0.62 362.2 0.98 ;
      RECT  363.78 0.62 364.285 0.98 ;
      RECT  365.865 0.62 368.04 0.98 ;
      RECT  369.62 0.62 370.525 0.98 ;
      RECT  372.105 0.62 373.88 0.98 ;
      RECT  375.46 0.62 376.765 0.98 ;
      RECT  378.345 0.62 379.72 0.98 ;
      RECT  381.3 0.62 383.005 0.98 ;
      RECT  384.585 0.62 385.56 0.98 ;
      RECT  387.14 0.62 389.245 0.98 ;
      RECT  390.825 0.62 391.4 0.98 ;
      RECT  392.98 0.62 395.435 0.98 ;
      RECT  397.015 0.62 397.24 0.98 ;
      RECT  398.82 0.62 401.04 0.98 ;
      RECT  402.62 0.62 403.08 0.98 ;
      RECT  404.66 0.62 407.115 0.98 ;
      RECT  408.695 0.62 408.92 0.98 ;
      RECT  410.5 0.62 412.955 0.98 ;
      RECT  414.535 0.62 414.76 0.98 ;
      RECT  423.405 0.62 426.44 0.98 ;
      RECT  428.71 0.62 432.28 0.98 ;
      RECT  434.565 0.62 438.12 0.98 ;
      RECT  440.745 0.62 443.96 0.98 ;
      RECT  446.985 0.62 449.8 0.98 ;
      RECT  451.38 0.62 451.645 0.98 ;
      RECT  453.225 0.62 455.64 0.98 ;
      RECT  457.22 0.62 457.885 0.98 ;
      RECT  459.465 0.62 461.48 0.98 ;
      RECT  463.06 0.62 464.125 0.98 ;
      RECT  465.705 0.62 467.32 0.98 ;
      RECT  468.9 0.62 470.365 0.98 ;
      RECT  471.945 0.62 473.16 0.98 ;
      RECT  474.74 0.62 476.605 0.98 ;
      RECT  478.185 0.62 479.0 0.98 ;
      RECT  480.58 0.62 482.845 0.98 ;
      RECT  484.425 0.62 484.84 0.98 ;
      RECT  486.42 0.62 488.875 0.98 ;
      RECT  490.455 0.62 490.68 0.98 ;
      RECT  492.26 0.62 494.64 0.98 ;
      RECT  496.22 0.62 496.52 0.98 ;
      RECT  498.1 0.62 500.555 0.98 ;
      RECT  502.135 0.62 502.36 0.98 ;
      RECT  510.765 0.62 514.04 0.98 ;
      RECT  516.31 0.62 519.88 0.98 ;
      RECT  522.15 0.62 525.72 0.98 ;
      RECT  528.105 0.62 531.56 0.98 ;
      RECT  534.345 0.62 537.4 0.98 ;
      RECT  538.98 0.62 539.005 0.98 ;
      RECT  540.585 0.62 543.24 0.98 ;
      RECT  544.82 0.62 545.245 0.98 ;
      RECT  546.825 0.62 549.08 0.98 ;
      RECT  550.66 0.62 551.485 0.98 ;
      RECT  553.065 0.62 554.92 0.98 ;
      RECT  556.5 0.62 557.725 0.98 ;
      RECT  559.305 0.62 560.76 0.98 ;
      RECT  562.34 0.62 563.965 0.98 ;
      RECT  565.545 0.62 566.6 0.98 ;
      RECT  568.18 0.62 570.205 0.98 ;
      RECT  571.785 0.62 572.44 0.98 ;
      RECT  574.02 0.62 576.445 0.98 ;
      RECT  578.025 0.62 578.28 0.98 ;
      RECT  579.86 0.62 582.315 0.98 ;
      RECT  583.895 0.62 584.12 0.98 ;
      RECT  585.7 0.62 588.155 0.98 ;
      RECT  589.735 0.62 589.96 0.98 ;
      RECT  591.54 0.62 593.995 0.98 ;
      RECT  595.575 0.62 595.8 0.98 ;
      RECT  604.365 0.62 607.48 0.98 ;
      RECT  609.75 0.62 613.32 0.98 ;
      RECT  615.59 0.62 619.16 0.98 ;
      RECT  621.705 0.62 625.0 0.98 ;
      RECT  627.945 0.62 630.84 0.98 ;
      RECT  632.42 0.62 632.605 0.98 ;
      RECT  634.185 0.62 636.68 0.98 ;
      RECT  638.26 0.62 638.845 0.98 ;
      RECT  640.425 0.62 642.52 0.98 ;
      RECT  644.1 0.62 645.085 0.98 ;
      RECT  646.665 0.62 648.36 0.98 ;
      RECT  649.94 0.62 651.325 0.98 ;
      RECT  652.905 0.62 654.2 0.98 ;
      RECT  655.78 0.62 657.565 0.98 ;
      RECT  659.145 0.62 660.04 0.98 ;
      RECT  661.62 0.62 663.805 0.98 ;
      RECT  665.385 0.62 665.88 0.98 ;
      RECT  667.46 0.62 669.915 0.98 ;
      RECT  671.495 0.62 671.72 0.98 ;
      RECT  673.3 0.62 675.6 0.98 ;
      RECT  677.18 0.62 677.56 0.98 ;
      RECT  679.14 0.62 681.595 0.98 ;
      RECT  683.175 0.62 683.4 0.98 ;
      RECT  691.725 0.62 695.08 0.98 ;
      RECT  697.35 0.62 700.92 0.98 ;
      RECT  703.19 0.62 706.76 0.98 ;
      RECT  709.065 0.62 712.6 0.98 ;
      RECT  715.305 0.62 718.44 0.98 ;
      RECT  721.545 0.62 724.28 0.98 ;
      RECT  725.86 0.62 726.205 0.98 ;
      RECT  727.785 0.62 730.12 0.98 ;
      RECT  731.7 0.62 732.445 0.98 ;
      RECT  734.025 0.62 735.96 0.98 ;
      RECT  737.54 0.62 738.685 0.98 ;
      RECT  740.265 0.62 741.8 0.98 ;
      RECT  743.38 0.62 744.925 0.98 ;
      RECT  746.505 0.62 747.64 0.98 ;
      RECT  749.22 0.62 751.165 0.98 ;
      RECT  752.745 0.62 753.48 0.98 ;
      RECT  755.06 0.62 757.405 0.98 ;
      RECT  758.985 0.62 759.32 0.98 ;
      RECT  760.9 0.62 763.355 0.98 ;
      RECT  764.935 0.62 765.16 0.98 ;
      RECT  766.74 0.62 769.195 0.98 ;
      RECT  770.775 0.62 771.0 0.98 ;
      RECT  772.58 0.62 775.035 0.98 ;
      RECT  776.615 0.62 776.84 0.98 ;
      RECT  785.325 0.62 788.52 0.98 ;
      RECT  790.79 0.62 794.36 0.98 ;
      RECT  796.63 0.62 800.2 0.98 ;
      RECT  802.665 0.62 806.04 0.98 ;
      RECT  808.905 0.62 811.88 0.98 ;
      RECT  813.46 0.62 813.565 0.98 ;
      RECT  815.145 0.62 817.72 0.98 ;
      RECT  819.3 0.62 819.805 0.98 ;
      RECT  821.385 0.62 823.56 0.98 ;
      RECT  825.14 0.62 826.045 0.98 ;
      RECT  827.625 0.62 829.4 0.98 ;
      RECT  830.98 0.62 832.285 0.98 ;
      RECT  833.865 0.62 835.24 0.98 ;
      RECT  836.82 0.62 838.525 0.98 ;
      RECT  840.105 0.62 841.08 0.98 ;
      RECT  842.66 0.62 844.765 0.98 ;
      RECT  846.345 0.62 846.92 0.98 ;
      RECT  848.5 0.62 850.955 0.98 ;
      RECT  852.535 0.62 852.76 0.98 ;
      RECT  854.34 0.62 856.56 0.98 ;
      RECT  858.14 0.62 858.6 0.98 ;
      RECT  860.18 0.62 862.635 0.98 ;
      RECT  864.215 0.62 864.44 0.98 ;
      RECT  866.02 0.62 868.475 0.98 ;
      RECT  870.055 0.62 870.28 0.98 ;
      RECT  878.925 0.62 881.96 0.98 ;
      RECT  884.23 0.62 887.8 0.98 ;
      RECT  890.085 0.62 893.64 0.98 ;
      RECT  896.265 0.62 899.48 0.98 ;
      RECT  902.505 0.62 905.32 0.98 ;
      RECT  906.9 0.62 907.165 0.98 ;
      RECT  908.745 0.62 911.16 0.98 ;
      RECT  912.74 0.62 913.405 0.98 ;
      RECT  914.985 0.62 917.0 0.98 ;
      RECT  918.58 0.62 919.645 0.98 ;
      RECT  921.225 0.62 922.84 0.98 ;
      RECT  924.42 0.62 925.885 0.98 ;
      RECT  927.465 0.62 928.68 0.98 ;
      RECT  930.26 0.62 932.125 0.98 ;
      RECT  933.705 0.62 934.52 0.98 ;
      RECT  936.1 0.62 938.365 0.98 ;
      RECT  939.945 0.62 940.36 0.98 ;
      RECT  941.94 0.62 944.395 0.98 ;
      RECT  945.975 0.62 946.2 0.98 ;
      RECT  947.78 0.62 950.16 0.98 ;
      RECT  951.74 0.62 952.04 0.98 ;
      RECT  953.62 0.62 956.075 0.98 ;
      RECT  957.655 0.62 957.88 0.98 ;
      RECT  966.285 0.62 969.56 0.98 ;
      RECT  971.83 0.62 975.4 0.98 ;
      RECT  977.67 0.62 981.24 0.98 ;
      RECT  983.625 0.62 987.08 0.98 ;
      RECT  989.865 0.62 992.92 0.98 ;
      RECT  994.5 0.62 994.525 0.98 ;
      RECT  996.105 0.62 998.76 0.98 ;
      RECT  1000.34 0.62 1000.765 0.98 ;
      RECT  1002.345 0.62 1004.6 0.98 ;
      RECT  1006.18 0.62 1007.005 0.98 ;
      RECT  1008.585 0.62 1010.44 0.98 ;
      RECT  1012.02 0.62 1013.245 0.98 ;
      RECT  1014.825 0.62 1016.28 0.98 ;
      RECT  1017.86 0.62 1019.485 0.98 ;
      RECT  1021.065 0.62 1022.12 0.98 ;
      RECT  1023.7 0.62 1025.725 0.98 ;
      RECT  1027.305 0.62 1027.96 0.98 ;
      RECT  1029.54 0.62 1031.965 0.98 ;
      RECT  1033.545 0.62 1033.8 0.98 ;
      RECT  1035.38 0.62 1037.835 0.98 ;
      RECT  1039.415 0.62 1039.64 0.98 ;
      RECT  1041.22 0.62 1043.675 0.98 ;
      RECT  1045.255 0.62 1045.48 0.98 ;
      RECT  1047.06 0.62 1049.515 0.98 ;
      RECT  1051.095 0.62 1051.32 0.98 ;
      RECT  1059.885 0.62 1063.0 0.98 ;
      RECT  1065.27 0.62 1068.84 0.98 ;
      RECT  1071.11 0.62 1074.68 0.98 ;
      RECT  1077.225 0.62 1080.52 0.98 ;
      RECT  1083.465 0.62 1086.36 0.98 ;
      RECT  1087.94 0.62 1088.125 0.98 ;
      RECT  1089.705 0.62 1092.2 0.98 ;
      RECT  1093.78 0.62 1094.365 0.98 ;
      RECT  1095.945 0.62 1098.04 0.98 ;
      RECT  1099.62 0.62 1100.605 0.98 ;
      RECT  1102.185 0.62 1103.88 0.98 ;
      RECT  1105.46 0.62 1106.845 0.98 ;
      RECT  1108.425 0.62 1109.72 0.98 ;
      RECT  1111.3 0.62 1113.085 0.98 ;
      RECT  1114.665 0.62 1115.56 0.98 ;
      RECT  1117.14 0.62 1119.325 0.98 ;
      RECT  1120.905 0.62 1121.4 0.98 ;
      RECT  1122.98 0.62 1125.435 0.98 ;
      RECT  1127.015 0.62 1127.24 0.98 ;
      RECT  1128.82 0.62 1131.12 0.98 ;
      RECT  1132.7 0.62 1133.08 0.98 ;
      RECT  1134.66 0.62 1137.115 0.98 ;
      RECT  1138.695 0.62 1138.92 0.98 ;
      RECT  1147.245 0.62 1150.6 0.98 ;
      RECT  1152.87 0.62 1156.44 0.98 ;
      RECT  1158.71 0.62 1162.28 0.98 ;
      RECT  1164.585 0.62 1168.12 0.98 ;
      RECT  1170.825 0.62 1173.96 0.98 ;
      RECT  1177.065 0.62 1179.8 0.98 ;
      RECT  1181.38 0.62 1181.725 0.98 ;
      RECT  1183.305 0.62 1185.64 0.98 ;
      RECT  1187.22 0.62 1187.965 0.98 ;
      RECT  1189.545 0.62 1191.48 0.98 ;
      RECT  1193.06 0.62 1194.205 0.98 ;
      RECT  1195.785 0.62 1197.32 0.98 ;
      RECT  1198.9 0.62 1200.445 0.98 ;
      RECT  1202.025 0.62 1203.16 0.98 ;
      RECT  1204.74 0.62 1206.685 0.98 ;
      RECT  1208.265 0.62 1209.0 0.98 ;
      RECT  1210.58 0.62 1212.925 0.98 ;
      RECT  1214.505 0.62 1214.84 0.98 ;
      RECT  1216.42 0.62 1218.875 0.98 ;
      RECT  1220.455 0.62 1220.68 0.98 ;
      RECT  1222.26 0.62 1224.715 0.98 ;
      RECT  1226.295 0.62 1226.52 0.98 ;
      RECT  1228.1 0.62 1230.555 0.98 ;
      RECT  1232.135 0.62 1232.36 0.98 ;
      RECT  1240.845 0.62 1244.04 0.98 ;
      RECT  1246.31 0.62 1249.88 0.98 ;
      RECT  1252.15 0.62 1255.72 0.98 ;
      RECT  1258.185 0.62 1261.56 0.98 ;
      RECT  1264.425 0.62 1267.4 0.98 ;
      RECT  1268.98 0.62 1269.085 0.98 ;
      RECT  1270.665 0.62 1273.24 0.98 ;
      RECT  1274.82 0.62 1275.325 0.98 ;
      RECT  1276.905 0.62 1279.08 0.98 ;
      RECT  1280.66 0.62 1281.565 0.98 ;
      RECT  1283.145 0.62 1284.92 0.98 ;
      RECT  1286.5 0.62 1287.805 0.98 ;
      RECT  1289.385 0.62 1290.76 0.98 ;
      RECT  1292.34 0.62 1294.045 0.98 ;
      RECT  1295.625 0.62 1296.6 0.98 ;
      RECT  1298.18 0.62 1300.285 0.98 ;
      RECT  1301.865 0.62 1302.44 0.98 ;
      RECT  1304.02 0.62 1306.475 0.98 ;
      RECT  1308.055 0.62 1308.28 0.98 ;
      RECT  1309.86 0.62 1312.08 0.98 ;
      RECT  1313.66 0.62 1314.12 0.98 ;
      RECT  1315.7 0.62 1318.155 0.98 ;
      RECT  1319.735 0.62 1319.96 0.98 ;
      RECT  1321.54 0.62 1323.995 0.98 ;
      RECT  1325.575 0.62 1325.8 0.98 ;
      RECT  1334.445 0.62 1337.48 0.98 ;
      RECT  1339.75 0.62 1343.32 0.98 ;
      RECT  1345.605 0.62 1349.16 0.98 ;
      RECT  1351.785 0.62 1355.0 0.98 ;
      RECT  1358.025 0.62 1360.84 0.98 ;
      RECT  1362.42 0.62 1362.685 0.98 ;
      RECT  1364.265 0.62 1366.68 0.98 ;
      RECT  1368.26 0.62 1368.925 0.98 ;
      RECT  1370.505 0.62 1372.52 0.98 ;
      RECT  1374.1 0.62 1375.165 0.98 ;
      RECT  1376.745 0.62 1378.36 0.98 ;
      RECT  1379.94 0.62 1381.405 0.98 ;
      RECT  1382.985 0.62 1384.2 0.98 ;
      RECT  1385.78 0.62 1387.645 0.98 ;
      RECT  1389.225 0.62 1390.04 0.98 ;
      RECT  1391.62 0.62 1393.885 0.98 ;
      RECT  1395.465 0.62 1395.88 0.98 ;
      RECT  1397.46 0.62 1399.915 0.98 ;
      RECT  1401.495 0.62 1401.72 0.98 ;
      RECT  1403.3 0.62 1405.68 0.98 ;
      RECT  1407.26 0.62 1407.56 0.98 ;
      RECT  1409.14 0.62 1411.595 0.98 ;
      RECT  1413.175 0.62 1413.4 0.98 ;
      RECT  1421.805 0.62 1425.08 0.98 ;
      RECT  1427.35 0.62 1430.92 0.98 ;
      RECT  1433.19 0.62 1436.76 0.98 ;
      RECT  1439.145 0.62 1442.6 0.98 ;
      RECT  1445.385 0.62 1448.44 0.98 ;
      RECT  1450.02 0.62 1450.045 0.98 ;
      RECT  1451.625 0.62 1454.28 0.98 ;
      RECT  1455.86 0.62 1456.285 0.98 ;
      RECT  1457.865 0.62 1460.12 0.98 ;
      RECT  1461.7 0.62 1462.525 0.98 ;
      RECT  1464.105 0.62 1465.96 0.98 ;
      RECT  1467.54 0.62 1468.765 0.98 ;
      RECT  1470.345 0.62 1471.8 0.98 ;
      RECT  1473.38 0.62 1475.005 0.98 ;
      RECT  1476.585 0.62 1477.64 0.98 ;
      RECT  1479.22 0.62 1481.245 0.98 ;
      RECT  1482.825 0.62 1483.48 0.98 ;
      RECT  1485.06 0.62 1487.485 0.98 ;
      RECT  1489.065 0.62 1489.32 0.98 ;
      RECT  1490.9 0.62 1493.355 0.98 ;
      RECT  1494.935 0.62 1495.16 0.98 ;
      RECT  1496.74 0.62 1499.195 0.98 ;
      RECT  1500.775 0.62 1501.0 0.98 ;
      RECT  1502.58 0.62 1505.035 0.98 ;
      RECT  1506.615 0.62 1506.84 0.98 ;
      RECT  1515.405 0.62 1518.52 0.98 ;
      RECT  1520.79 0.62 1524.36 0.98 ;
      RECT  1526.63 0.62 1530.2 0.98 ;
      RECT  1532.745 0.62 1536.04 0.98 ;
      RECT  1538.985 0.62 1541.88 0.98 ;
      RECT  1543.46 0.62 1543.645 0.98 ;
      RECT  1545.225 0.62 1547.72 0.98 ;
      RECT  1549.3 0.62 1549.885 0.98 ;
      RECT  1551.465 0.62 1553.56 0.98 ;
      RECT  1555.14 0.62 1556.125 0.98 ;
      RECT  1557.705 0.62 1559.4 0.98 ;
      RECT  1560.98 0.62 1562.365 0.98 ;
      RECT  1563.945 0.62 1565.24 0.98 ;
      RECT  1566.82 0.62 1568.605 0.98 ;
      RECT  1570.185 0.62 1571.08 0.98 ;
      RECT  1572.66 0.62 1574.845 0.98 ;
      RECT  1576.425 0.62 1576.92 0.98 ;
      RECT  1578.5 0.62 1580.955 0.98 ;
      RECT  1582.535 0.62 1582.76 0.98 ;
      RECT  1584.34 0.62 1586.64 0.98 ;
      RECT  1588.22 0.62 1588.6 0.98 ;
      RECT  1590.18 0.62 1592.635 0.98 ;
      RECT  1594.215 0.62 1594.44 0.98 ;
      RECT  1602.765 0.62 1606.12 0.98 ;
      RECT  1608.39 0.62 1611.96 0.98 ;
      RECT  1614.23 0.62 1617.8 0.98 ;
      RECT  1620.105 0.62 1623.64 0.98 ;
      RECT  1626.345 0.62 1629.48 0.98 ;
      RECT  1632.585 0.62 1635.32 0.98 ;
      RECT  1636.9 0.62 1637.245 0.98 ;
      RECT  1638.825 0.62 1641.16 0.98 ;
      RECT  1642.74 0.62 1643.485 0.98 ;
      RECT  1645.065 0.62 1647.0 0.98 ;
      RECT  1648.58 0.62 1649.725 0.98 ;
      RECT  1651.305 0.62 1652.84 0.98 ;
      RECT  1654.42 0.62 1655.965 0.98 ;
      RECT  1657.545 0.62 1658.68 0.98 ;
      RECT  1660.26 0.62 1662.205 0.98 ;
      RECT  1663.785 0.62 1664.52 0.98 ;
      RECT  1666.1 0.62 1668.445 0.98 ;
      RECT  1670.025 0.62 1670.36 0.98 ;
      RECT  1671.94 0.62 1674.395 0.98 ;
      RECT  1675.975 0.62 1676.2 0.98 ;
      RECT  1677.78 0.62 1680.235 0.98 ;
      RECT  1681.815 0.62 1682.04 0.98 ;
      RECT  1683.62 0.62 1686.075 0.98 ;
      RECT  1687.655 0.62 1687.88 0.98 ;
      RECT  1696.365 0.62 1699.56 0.98 ;
      RECT  1701.83 0.62 1705.4 0.98 ;
      RECT  1707.67 0.62 1711.24 0.98 ;
      RECT  1713.705 0.62 1717.08 0.98 ;
      RECT  1719.945 0.62 1722.92 0.98 ;
      RECT  1724.5 0.62 1724.605 0.98 ;
      RECT  1726.185 0.62 1728.76 0.98 ;
      RECT  1730.34 0.62 1730.845 0.98 ;
      RECT  1732.425 0.62 1734.6 0.98 ;
      RECT  1736.18 0.62 1737.085 0.98 ;
      RECT  1738.665 0.62 1740.44 0.98 ;
      RECT  1742.02 0.62 1743.325 0.98 ;
      RECT  1744.905 0.62 1746.28 0.98 ;
      RECT  1747.86 0.62 1749.565 0.98 ;
      RECT  1751.145 0.62 1752.12 0.98 ;
      RECT  1753.7 0.62 1755.805 0.98 ;
      RECT  1757.385 0.62 1757.96 0.98 ;
      RECT  1759.54 0.62 1761.995 0.98 ;
      RECT  1763.575 0.62 1768.285 0.98 ;
      RECT  1769.865 0.62 1774.525 0.98 ;
      RECT  1776.105 0.62 1780.765 0.98 ;
      RECT  1782.345 0.62 1787.005 0.98 ;
      RECT  1788.585 0.62 1793.245 0.98 ;
      RECT  1794.825 0.62 1799.485 0.98 ;
      RECT  1801.065 0.62 1805.725 0.98 ;
      RECT  1807.305 0.62 1811.965 0.98 ;
      RECT  1813.545 0.62 1818.205 0.98 ;
      RECT  1819.785 0.62 1824.445 0.98 ;
      RECT  1826.025 0.62 1830.685 0.98 ;
      RECT  1832.265 0.62 1836.925 0.98 ;
      RECT  1838.505 0.62 1843.165 0.98 ;
      RECT  1844.745 0.62 1849.405 0.98 ;
      RECT  1850.985 0.62 1855.645 0.98 ;
      RECT  1857.225 0.62 1861.885 0.98 ;
      RECT  1863.465 0.62 1868.125 0.98 ;
      RECT  1869.705 0.62 1874.365 0.98 ;
      RECT  1875.945 0.62 1880.605 0.98 ;
      RECT  1882.185 0.62 1886.845 0.98 ;
      RECT  1888.425 0.62 1893.085 0.98 ;
      RECT  1894.665 0.62 1899.325 0.98 ;
      RECT  1900.905 0.62 1905.565 0.98 ;
      RECT  1907.145 0.62 1911.805 0.98 ;
      RECT  1913.385 0.62 1986.875 0.98 ;
      RECT  258.66 225.455 314.425 225.815 ;
      RECT  316.005 225.455 320.665 225.815 ;
      RECT  322.245 225.455 326.905 225.815 ;
      RECT  328.485 225.455 333.145 225.815 ;
      RECT  334.725 225.455 339.385 225.815 ;
      RECT  340.965 225.455 345.625 225.815 ;
      RECT  347.205 225.455 351.865 225.815 ;
      RECT  353.445 225.455 358.105 225.815 ;
      RECT  359.685 225.455 364.345 225.815 ;
      RECT  365.925 225.455 370.585 225.815 ;
      RECT  372.165 225.455 376.825 225.815 ;
      RECT  378.405 225.455 383.065 225.815 ;
      RECT  384.645 225.455 389.305 225.815 ;
      RECT  390.885 225.455 395.545 225.815 ;
      RECT  397.125 225.455 401.785 225.815 ;
      RECT  403.365 225.455 408.025 225.815 ;
      RECT  409.605 225.455 414.265 225.815 ;
      RECT  415.845 225.455 420.505 225.815 ;
      RECT  422.085 225.455 426.745 225.815 ;
      RECT  428.325 225.455 432.985 225.815 ;
      RECT  434.565 225.455 439.225 225.815 ;
      RECT  440.805 225.455 445.465 225.815 ;
      RECT  447.045 225.455 451.705 225.815 ;
      RECT  453.285 225.455 457.945 225.815 ;
      RECT  459.525 225.455 464.185 225.815 ;
      RECT  465.765 225.455 470.425 225.815 ;
      RECT  472.005 225.455 476.665 225.815 ;
      RECT  478.245 225.455 482.905 225.815 ;
      RECT  484.485 225.455 489.145 225.815 ;
      RECT  490.725 225.455 495.385 225.815 ;
      RECT  496.965 225.455 501.625 225.815 ;
      RECT  503.205 225.455 507.865 225.815 ;
      RECT  509.445 225.455 514.105 225.815 ;
      RECT  515.685 225.455 520.345 225.815 ;
      RECT  521.925 225.455 526.585 225.815 ;
      RECT  528.165 225.455 532.825 225.815 ;
      RECT  534.405 225.455 539.065 225.815 ;
      RECT  540.645 225.455 545.305 225.815 ;
      RECT  546.885 225.455 551.545 225.815 ;
      RECT  553.125 225.455 557.785 225.815 ;
      RECT  559.365 225.455 564.025 225.815 ;
      RECT  565.605 225.455 570.265 225.815 ;
      RECT  571.845 225.455 576.505 225.815 ;
      RECT  578.085 225.455 582.745 225.815 ;
      RECT  584.325 225.455 588.985 225.815 ;
      RECT  590.565 225.455 595.225 225.815 ;
      RECT  596.805 225.455 601.465 225.815 ;
      RECT  603.045 225.455 607.705 225.815 ;
      RECT  609.285 225.455 613.945 225.815 ;
      RECT  615.525 225.455 620.185 225.815 ;
      RECT  621.765 225.455 626.425 225.815 ;
      RECT  628.005 225.455 632.665 225.815 ;
      RECT  634.245 225.455 638.905 225.815 ;
      RECT  640.485 225.455 645.145 225.815 ;
      RECT  646.725 225.455 651.385 225.815 ;
      RECT  652.965 225.455 657.625 225.815 ;
      RECT  659.205 225.455 663.865 225.815 ;
      RECT  665.445 225.455 670.105 225.815 ;
      RECT  671.685 225.455 676.345 225.815 ;
      RECT  677.925 225.455 682.585 225.815 ;
      RECT  684.165 225.455 688.825 225.815 ;
      RECT  690.405 225.455 695.065 225.815 ;
      RECT  696.645 225.455 701.305 225.815 ;
      RECT  702.885 225.455 707.545 225.815 ;
      RECT  709.125 225.455 713.785 225.815 ;
      RECT  715.365 225.455 720.025 225.815 ;
      RECT  721.605 225.455 726.265 225.815 ;
      RECT  727.845 225.455 732.505 225.815 ;
      RECT  734.085 225.455 738.745 225.815 ;
      RECT  740.325 225.455 744.985 225.815 ;
      RECT  746.565 225.455 751.225 225.815 ;
      RECT  752.805 225.455 757.465 225.815 ;
      RECT  759.045 225.455 763.705 225.815 ;
      RECT  765.285 225.455 769.945 225.815 ;
      RECT  771.525 225.455 776.185 225.815 ;
      RECT  777.765 225.455 782.425 225.815 ;
      RECT  784.005 225.455 788.665 225.815 ;
      RECT  790.245 225.455 794.905 225.815 ;
      RECT  796.485 225.455 801.145 225.815 ;
      RECT  802.725 225.455 807.385 225.815 ;
      RECT  808.965 225.455 813.625 225.815 ;
      RECT  815.205 225.455 819.865 225.815 ;
      RECT  821.445 225.455 826.105 225.815 ;
      RECT  827.685 225.455 832.345 225.815 ;
      RECT  833.925 225.455 838.585 225.815 ;
      RECT  840.165 225.455 844.825 225.815 ;
      RECT  846.405 225.455 851.065 225.815 ;
      RECT  852.645 225.455 857.305 225.815 ;
      RECT  858.885 225.455 863.545 225.815 ;
      RECT  865.125 225.455 869.785 225.815 ;
      RECT  871.365 225.455 876.025 225.815 ;
      RECT  877.605 225.455 882.265 225.815 ;
      RECT  883.845 225.455 888.505 225.815 ;
      RECT  890.085 225.455 894.745 225.815 ;
      RECT  896.325 225.455 900.985 225.815 ;
      RECT  902.565 225.455 907.225 225.815 ;
      RECT  908.805 225.455 913.465 225.815 ;
      RECT  915.045 225.455 919.705 225.815 ;
      RECT  921.285 225.455 925.945 225.815 ;
      RECT  927.525 225.455 932.185 225.815 ;
      RECT  933.765 225.455 938.425 225.815 ;
      RECT  940.005 225.455 944.665 225.815 ;
      RECT  946.245 225.455 950.905 225.815 ;
      RECT  952.485 225.455 957.145 225.815 ;
      RECT  958.725 225.455 963.385 225.815 ;
      RECT  964.965 225.455 969.625 225.815 ;
      RECT  971.205 225.455 975.865 225.815 ;
      RECT  977.445 225.455 982.105 225.815 ;
      RECT  983.685 225.455 988.345 225.815 ;
      RECT  989.925 225.455 994.585 225.815 ;
      RECT  996.165 225.455 1000.825 225.815 ;
      RECT  1002.405 225.455 1007.065 225.815 ;
      RECT  1008.645 225.455 1013.305 225.815 ;
      RECT  1014.885 225.455 1019.545 225.815 ;
      RECT  1021.125 225.455 1025.785 225.815 ;
      RECT  1027.365 225.455 1032.025 225.815 ;
      RECT  1033.605 225.455 1038.265 225.815 ;
      RECT  1039.845 225.455 1044.505 225.815 ;
      RECT  1046.085 225.455 1050.745 225.815 ;
      RECT  1052.325 225.455 1056.985 225.815 ;
      RECT  1058.565 225.455 1063.225 225.815 ;
      RECT  1064.805 225.455 1069.465 225.815 ;
      RECT  1071.045 225.455 1075.705 225.815 ;
      RECT  1077.285 225.455 1081.945 225.815 ;
      RECT  1083.525 225.455 1088.185 225.815 ;
      RECT  1089.765 225.455 1094.425 225.815 ;
      RECT  1096.005 225.455 1100.665 225.815 ;
      RECT  1102.245 225.455 1106.905 225.815 ;
      RECT  1108.485 225.455 1113.145 225.815 ;
      RECT  1114.725 225.455 1119.385 225.815 ;
      RECT  1120.965 225.455 1125.625 225.815 ;
      RECT  1127.205 225.455 1131.865 225.815 ;
      RECT  1133.445 225.455 1138.105 225.815 ;
      RECT  1139.685 225.455 1144.345 225.815 ;
      RECT  1145.925 225.455 1150.585 225.815 ;
      RECT  1152.165 225.455 1156.825 225.815 ;
      RECT  1158.405 225.455 1163.065 225.815 ;
      RECT  1164.645 225.455 1169.305 225.815 ;
      RECT  1170.885 225.455 1175.545 225.815 ;
      RECT  1177.125 225.455 1181.785 225.815 ;
      RECT  1183.365 225.455 1188.025 225.815 ;
      RECT  1189.605 225.455 1194.265 225.815 ;
      RECT  1195.845 225.455 1200.505 225.815 ;
      RECT  1202.085 225.455 1206.745 225.815 ;
      RECT  1208.325 225.455 1212.985 225.815 ;
      RECT  1214.565 225.455 1219.225 225.815 ;
      RECT  1220.805 225.455 1225.465 225.815 ;
      RECT  1227.045 225.455 1231.705 225.815 ;
      RECT  1233.285 225.455 1237.945 225.815 ;
      RECT  1239.525 225.455 1244.185 225.815 ;
      RECT  1245.765 225.455 1250.425 225.815 ;
      RECT  1252.005 225.455 1256.665 225.815 ;
      RECT  1258.245 225.455 1262.905 225.815 ;
      RECT  1264.485 225.455 1269.145 225.815 ;
      RECT  1270.725 225.455 1275.385 225.815 ;
      RECT  1276.965 225.455 1281.625 225.815 ;
      RECT  1283.205 225.455 1287.865 225.815 ;
      RECT  1289.445 225.455 1294.105 225.815 ;
      RECT  1295.685 225.455 1300.345 225.815 ;
      RECT  1301.925 225.455 1306.585 225.815 ;
      RECT  1308.165 225.455 1312.825 225.815 ;
      RECT  1314.405 225.455 1319.065 225.815 ;
      RECT  1320.645 225.455 1325.305 225.815 ;
      RECT  1326.885 225.455 1331.545 225.815 ;
      RECT  1333.125 225.455 1337.785 225.815 ;
      RECT  1339.365 225.455 1344.025 225.815 ;
      RECT  1345.605 225.455 1350.265 225.815 ;
      RECT  1351.845 225.455 1356.505 225.815 ;
      RECT  1358.085 225.455 1362.745 225.815 ;
      RECT  1364.325 225.455 1368.985 225.815 ;
      RECT  1370.565 225.455 1375.225 225.815 ;
      RECT  1376.805 225.455 1381.465 225.815 ;
      RECT  1383.045 225.455 1387.705 225.815 ;
      RECT  1389.285 225.455 1393.945 225.815 ;
      RECT  1395.525 225.455 1400.185 225.815 ;
      RECT  1401.765 225.455 1406.425 225.815 ;
      RECT  1408.005 225.455 1412.665 225.815 ;
      RECT  1414.245 225.455 1418.905 225.815 ;
      RECT  1420.485 225.455 1425.145 225.815 ;
      RECT  1426.725 225.455 1431.385 225.815 ;
      RECT  1432.965 225.455 1437.625 225.815 ;
      RECT  1439.205 225.455 1443.865 225.815 ;
      RECT  1445.445 225.455 1450.105 225.815 ;
      RECT  1451.685 225.455 1456.345 225.815 ;
      RECT  1457.925 225.455 1462.585 225.815 ;
      RECT  1464.165 225.455 1468.825 225.815 ;
      RECT  1470.405 225.455 1475.065 225.815 ;
      RECT  1476.645 225.455 1481.305 225.815 ;
      RECT  1482.885 225.455 1487.545 225.815 ;
      RECT  1489.125 225.455 1493.785 225.815 ;
      RECT  1495.365 225.455 1500.025 225.815 ;
      RECT  1501.605 225.455 1506.265 225.815 ;
      RECT  1507.845 225.455 1512.505 225.815 ;
      RECT  1514.085 225.455 1518.745 225.815 ;
      RECT  1520.325 225.455 1524.985 225.815 ;
      RECT  1526.565 225.455 1531.225 225.815 ;
      RECT  1532.805 225.455 1537.465 225.815 ;
      RECT  1539.045 225.455 1543.705 225.815 ;
      RECT  1545.285 225.455 1549.945 225.815 ;
      RECT  1551.525 225.455 1556.185 225.815 ;
      RECT  1557.765 225.455 1562.425 225.815 ;
      RECT  1564.005 225.455 1568.665 225.815 ;
      RECT  1570.245 225.455 1574.905 225.815 ;
      RECT  1576.485 225.455 1581.145 225.815 ;
      RECT  1582.725 225.455 1587.385 225.815 ;
      RECT  1588.965 225.455 1593.625 225.815 ;
      RECT  1595.205 225.455 1599.865 225.815 ;
      RECT  1601.445 225.455 1606.105 225.815 ;
      RECT  1607.685 225.455 1612.345 225.815 ;
      RECT  1613.925 225.455 1618.585 225.815 ;
      RECT  1620.165 225.455 1624.825 225.815 ;
      RECT  1626.405 225.455 1631.065 225.815 ;
      RECT  1632.645 225.455 1637.305 225.815 ;
      RECT  1638.885 225.455 1643.545 225.815 ;
      RECT  1645.125 225.455 1649.785 225.815 ;
      RECT  1651.365 225.455 1656.025 225.815 ;
      RECT  1657.605 225.455 1662.265 225.815 ;
      RECT  1663.845 225.455 1668.505 225.815 ;
      RECT  1670.085 225.455 1674.745 225.815 ;
      RECT  1676.325 225.455 1680.985 225.815 ;
      RECT  1682.565 225.455 1687.225 225.815 ;
      RECT  1688.805 225.455 1693.465 225.815 ;
      RECT  1695.045 225.455 1699.705 225.815 ;
      RECT  1701.285 225.455 1705.945 225.815 ;
      RECT  1707.525 225.455 1712.185 225.815 ;
      RECT  1713.765 225.455 1718.425 225.815 ;
      RECT  1720.005 225.455 1724.665 225.815 ;
      RECT  1726.245 225.455 1730.905 225.815 ;
      RECT  1732.485 225.455 1737.145 225.815 ;
      RECT  1738.725 225.455 1743.385 225.815 ;
      RECT  1744.965 225.455 1749.625 225.815 ;
      RECT  1751.205 225.455 1755.865 225.815 ;
      RECT  1757.445 225.455 1762.105 225.815 ;
      RECT  1763.685 225.455 1768.345 225.815 ;
      RECT  1769.925 225.455 1774.585 225.815 ;
      RECT  1776.165 225.455 1780.825 225.815 ;
      RECT  1782.405 225.455 1787.065 225.815 ;
      RECT  1788.645 225.455 1793.305 225.815 ;
      RECT  1794.885 225.455 1799.545 225.815 ;
      RECT  1801.125 225.455 1805.785 225.815 ;
      RECT  1807.365 225.455 1812.025 225.815 ;
      RECT  1813.605 225.455 1818.265 225.815 ;
      RECT  1819.845 225.455 1824.505 225.815 ;
      RECT  1826.085 225.455 1830.745 225.815 ;
      RECT  1832.325 225.455 1836.985 225.815 ;
      RECT  1838.565 225.455 1843.225 225.815 ;
      RECT  1844.805 225.455 1849.465 225.815 ;
      RECT  1851.045 225.455 1855.705 225.815 ;
      RECT  1857.285 225.455 1861.945 225.815 ;
      RECT  1863.525 225.455 1868.185 225.815 ;
      RECT  1869.765 225.455 1874.425 225.815 ;
      RECT  1876.005 225.455 1880.665 225.815 ;
      RECT  1882.245 225.455 1886.905 225.815 ;
      RECT  1888.485 225.455 1893.145 225.815 ;
      RECT  1894.725 225.455 1899.385 225.815 ;
      RECT  1900.965 225.455 1905.625 225.815 ;
      RECT  1907.205 225.455 1911.865 225.815 ;
      RECT  1913.445 225.455 1971.48 225.815 ;
      RECT  2.34 0.62 251.24 0.98 ;
      RECT  2.34 225.455 237.33 225.815 ;
      RECT  1992.81 0.62 2226.42 0.98 ;
      RECT  2199.1 225.455 2226.42 225.815 ;
      RECT  1973.06 0.98 2222.94 2.88 ;
      RECT  1973.06 2.88 2222.94 223.555 ;
      RECT  1973.06 223.555 2222.94 225.455 ;
      RECT  2222.94 0.98 2225.88 2.88 ;
      RECT  2222.94 223.555 2225.88 225.455 ;
      RECT  2225.88 0.98 2226.42 2.88 ;
      RECT  2225.88 2.88 2226.42 223.555 ;
      RECT  2225.88 223.555 2226.42 225.455 ;
      RECT  2.34 0.98 2.88 2.88 ;
      RECT  2.34 2.88 2.88 223.555 ;
      RECT  2.34 223.555 2.88 225.455 ;
      RECT  2.88 0.98 5.82 2.88 ;
      RECT  2.88 223.555 5.82 225.455 ;
      RECT  5.82 0.98 237.33 2.88 ;
      RECT  5.82 2.88 237.33 223.555 ;
      RECT  5.82 223.555 237.33 225.455 ;
   END
END    id_memory_256x64
END    LIBRARY
